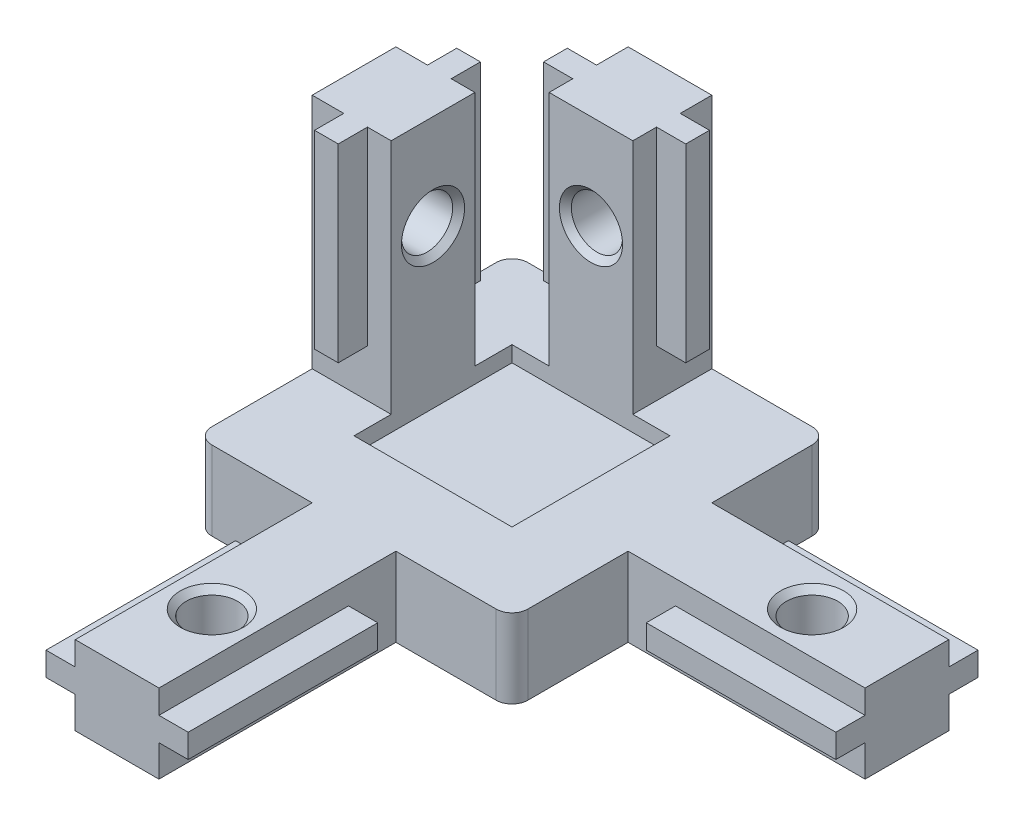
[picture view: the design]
ISO-10303-21;
HEADER;
FILE_DESCRIPTION(('STEP AP214'),'2;1');
FILE_NAME('part.step','',(''),(''),'','','');
FILE_SCHEMA(('AUTOMOTIVE_DESIGN { 1 0 10303 214 1 1 1 1 }'));
ENDSEC;
DATA;
#1=APPLICATION_CONTEXT('core data for automotive mechanical design processes');
#2=APPLICATION_PROTOCOL_DEFINITION('international standard','automotive_design',2000,#1);
#3=PRODUCT_CONTEXT('',#1,'mechanical');
#4=PRODUCT('Part','Part','',(#3));
#5=PRODUCT_RELATED_PRODUCT_CATEGORY('part','',(#4));
#6=PRODUCT_DEFINITION_FORMATION('','',#4);
#7=PRODUCT_DEFINITION_CONTEXT('part definition',#1,'design');
#8=PRODUCT_DEFINITION('design','',#6,#7);
#9=PRODUCT_DEFINITION_SHAPE('','',#8);
#10=(LENGTH_UNIT() NAMED_UNIT(*) SI_UNIT(.MILLI.,.METRE.));
#11=(NAMED_UNIT(*) PLANE_ANGLE_UNIT() SI_UNIT($,.RADIAN.));
#12=(NAMED_UNIT(*) SI_UNIT($,.STERADIAN.) SOLID_ANGLE_UNIT());
#13=UNCERTAINTY_MEASURE_WITH_UNIT(LENGTH_MEASURE(1.E-05),#10,'distance_accuracy_value','');
#14=(GEOMETRIC_REPRESENTATION_CONTEXT(3) GLOBAL_UNCERTAINTY_ASSIGNED_CONTEXT((#13)) GLOBAL_UNIT_ASSIGNED_CONTEXT((#10,
#11,#12)) REPRESENTATION_CONTEXT('',''));
#15=CARTESIAN_POINT('',(0.,0.,0.));
#16=DIRECTION('',(0.,0.,1.));
#17=DIRECTION('',(1.,0.,0.));
#18=AXIS2_PLACEMENT_3D('',#15,#16,#17);
#19=CARTESIAN_POINT('',(2.65,5.,35.));
#20=DIRECTION('',(0.,-1.,0.));
#21=DIRECTION('',(0.,0.,-1.));
#22=AXIS2_PLACEMENT_3D('',#19,#20,#21);
#23=PLANE('',#22);
#24=DIRECTION('',(0.,0.,1.));
#25=VECTOR('',#24,1.);
#26=CARTESIAN_POINT('',(-5.,5.,5.));
#27=LINE('',#26,#25);
#28=CARTESIAN_POINT('',(-5.,5.,5.));
#29=VERTEX_POINT('',#28);
#30=CARTESIAN_POINT('',(-5.,5.,7.35));
#31=VERTEX_POINT('',#30);
#32=EDGE_CURVE('E7',#29,#31,#27,.T.);
#33=ORIENTED_EDGE('',*,*,#32,.F.);
#34=DIRECTION('',(-1.,0.,0.));
#35=VECTOR('',#34,1.);
#36=CARTESIAN_POINT('',(-2.65,5.,5.));
#37=LINE('',#36,#35);
#38=CARTESIAN_POINT('',(-2.65,5.,5.));
#39=VERTEX_POINT('',#38);
#40=EDGE_CURVE('E14',#39,#29,#37,.T.);
#41=ORIENTED_EDGE('',*,*,#40,.F.);
#42=DIRECTION('',(0.,0.,1.));
#43=VECTOR('',#42,1.);
#44=CARTESIAN_POINT('',(-2.65,5.,0.));
#45=LINE('',#44,#43);
#46=CARTESIAN_POINT('',(-2.65,5.,0.));
#47=VERTEX_POINT('',#46);
#48=EDGE_CURVE('E21',#47,#39,#45,.T.);
#49=ORIENTED_EDGE('',*,*,#48,.F.);
#50=DIRECTION('',(-1.,0.,0.));
#51=VECTOR('',#50,1.);
#52=CARTESIAN_POINT('',(-2.65,5.,0.));
#53=LINE('',#52,#51);
#54=CARTESIAN_POINT('',(-9.,5.,0.));
#55=VERTEX_POINT('',#54);
#56=EDGE_CURVE('E28',#47,#55,#53,.T.);
#57=ORIENTED_EDGE('',*,*,#56,.T.);
#58=CARTESIAN_POINT('',(-9.,5.,1.00000000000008));
#59=DIRECTION('',(0.,1.,0.));
#60=DIRECTION('',(0.,0.,-1.));
#61=AXIS2_PLACEMENT_3D('',#58,#59,#60);
#62=CIRCLE('',#61,1.00000000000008);
#63=CARTESIAN_POINT('',(-10.,5.,1.));
#64=VERTEX_POINT('',#63);
#65=EDGE_CURVE('E35',#55,#64,#62,.T.);
#66=ORIENTED_EDGE('',*,*,#65,.T.);
#67=DIRECTION('',(0.,0.,1.));
#68=VECTOR('',#67,1.);
#69=CARTESIAN_POINT('',(-10.,5.,1.));
#70=LINE('',#69,#68);
#71=CARTESIAN_POINT('',(-10.,5.,7.35));
#72=VERTEX_POINT('',#71);
#73=EDGE_CURVE('E42',#64,#72,#70,.T.);
#74=ORIENTED_EDGE('',*,*,#73,.T.);
#75=DIRECTION('',(-1.,0.,0.));
#76=VECTOR('',#75,1.);
#77=CARTESIAN_POINT('',(-5.,5.,7.35));
#78=LINE('',#77,#76);
#79=EDGE_CURVE('E49',#31,#72,#78,.T.);
#80=ORIENTED_EDGE('',*,*,#79,.F.);
#81=EDGE_LOOP('',(#33,#41,#49,#57,#66,#74,#80));
#82=FACE_BOUND('',#81,.T.);
#83=ADVANCED_FACE('F55',(#82),#23,.F.);
#84=CARTESIAN_POINT('',(10.,5.,19.));
#85=DIRECTION('',(-1.,0.,0.));
#86=DIRECTION('',(0.,0.,1.));
#87=AXIS2_PLACEMENT_3D('',#84,#85,#86);
#88=PLANE('',#87);
#89=DIRECTION('',(0.,-1.,0.));
#90=VECTOR('',#89,1.);
#91=CARTESIAN_POINT('',(10.,5.,12.65));
#92=LINE('',#91,#90);
#93=CARTESIAN_POINT('',(10.,5.,12.65));
#94=VERTEX_POINT('',#93);
#95=CARTESIAN_POINT('',(10.,0.,12.65));
#96=VERTEX_POINT('',#95);
#97=EDGE_CURVE('E68',#94,#96,#92,.T.);
#98=ORIENTED_EDGE('',*,*,#97,.F.);
#99=DIRECTION('',(0.,0.,-1.));
#100=VECTOR('',#99,1.);
#101=CARTESIAN_POINT('',(10.,5.,19.));
#102=LINE('',#101,#100);
#103=CARTESIAN_POINT('',(10.,5.,19.));
#104=VERTEX_POINT('',#103);
#105=EDGE_CURVE('E75',#104,#94,#102,.T.);
#106=ORIENTED_EDGE('',*,*,#105,.F.);
#107=DIRECTION('',(0.,-1.,0.));
#108=VECTOR('',#107,1.);
#109=CARTESIAN_POINT('',(10.,5.,19.));
#110=LINE('',#109,#108);
#111=CARTESIAN_POINT('',(10.,0.,19.));
#112=VERTEX_POINT('',#111);
#113=EDGE_CURVE('E82',#104,#112,#110,.T.);
#114=ORIENTED_EDGE('',*,*,#113,.T.);
#115=DIRECTION('',(0.,0.,-1.));
#116=VECTOR('',#115,1.);
#117=CARTESIAN_POINT('',(10.,0.,19.));
#118=LINE('',#117,#116);
#119=EDGE_CURVE('E89',#112,#96,#118,.T.);
#120=ORIENTED_EDGE('',*,*,#119,.T.);
#121=EDGE_LOOP('',(#98,#106,#114,#120));
#122=FACE_BOUND('',#121,.T.);
#123=ADVANCED_FACE('F95',(#122),#88,.F.);
#124=DIRECTION('',(0.,1.,0.));
#125=VECTOR('',#124,1.);
#126=CARTESIAN_POINT('',(10.,0.,7.35));
#127=LINE('',#126,#125);
#128=CARTESIAN_POINT('',(10.,0.,7.35));
#129=VERTEX_POINT('',#128);
#130=CARTESIAN_POINT('',(10.,5.,7.35));
#131=VERTEX_POINT('',#130);
#132=EDGE_CURVE('E104',#129,#131,#127,.T.);
#133=ORIENTED_EDGE('',*,*,#132,.F.);
#134=DIRECTION('',(0.,0.,-1.));
#135=VECTOR('',#134,1.);
#136=CARTESIAN_POINT('',(10.,0.,7.35));
#137=LINE('',#136,#135);
#138=CARTESIAN_POINT('',(10.,0.,1.));
#139=VERTEX_POINT('',#138);
#140=EDGE_CURVE('E111',#129,#139,#137,.T.);
#141=ORIENTED_EDGE('',*,*,#140,.T.);
#142=DIRECTION('',(0.,-1.,0.));
#143=VECTOR('',#142,1.);
#144=CARTESIAN_POINT('',(10.,5.,1.));
#145=LINE('',#144,#143);
#146=CARTESIAN_POINT('',(10.,5.,1.));
#147=VERTEX_POINT('',#146);
#148=EDGE_CURVE('E118',#147,#139,#145,.T.);
#149=ORIENTED_EDGE('',*,*,#148,.F.);
#150=DIRECTION('',(0.,0.,-1.));
#151=VECTOR('',#150,1.);
#152=CARTESIAN_POINT('',(10.,5.,7.35));
#153=LINE('',#152,#151);
#154=EDGE_CURVE('E125',#131,#147,#153,.T.);
#155=ORIENTED_EDGE('',*,*,#154,.F.);
#156=EDGE_LOOP('',(#133,#141,#149,#155));
#157=FACE_BOUND('',#156,.T.);
#158=ADVANCED_FACE('F130',(#157),#88,.F.);
#159=CARTESIAN_POINT('',(19.,5.,10.));
#160=DIRECTION('',(0.,-1.,0.));
#161=DIRECTION('',(0.,0.,-1.));
#162=AXIS2_PLACEMENT_3D('',#159,#160,#161);
#163=CIRCLE('',#162,2.);
#164=CARTESIAN_POINT('',(19.,5.,8.));
#165=VERTEX_POINT('',#164);
#166=EDGE_CURVE('E137',#165,#165,#163,.T.);
#167=ORIENTED_EDGE('',*,*,#166,.T.);
#168=EDGE_LOOP('',(#167));
#169=FACE_BOUND('',#168,.T.);
#170=DIRECTION('',(0.,0.,-1.));
#171=VECTOR('',#170,1.);
#172=CARTESIAN_POINT('',(2.65,5.,5.));
#173=LINE('',#172,#171);
#174=CARTESIAN_POINT('',(2.65,5.,5.));
#175=VERTEX_POINT('',#174);
#176=CARTESIAN_POINT('',(2.65,5.,0.));
#177=VERTEX_POINT('',#176);
#178=EDGE_CURVE('E143',#175,#177,#173,.T.);
#179=ORIENTED_EDGE('',*,*,#178,.F.);
#180=DIRECTION('',(-1.,0.,0.));
#181=VECTOR('',#180,1.);
#182=CARTESIAN_POINT('',(5.,5.,5.));
#183=LINE('',#182,#181);
#184=CARTESIAN_POINT('',(5.,5.,5.));
#185=VERTEX_POINT('',#184);
#186=EDGE_CURVE('E150',#185,#175,#183,.T.);
#187=ORIENTED_EDGE('',*,*,#186,.F.);
#188=DIRECTION('',(0.,0.,-1.));
#189=VECTOR('',#188,1.);
#190=CARTESIAN_POINT('',(5.,5.,15.));
#191=LINE('',#190,#189);
#192=CARTESIAN_POINT('',(5.,5.,15.));
#193=VERTEX_POINT('',#192);
#194=EDGE_CURVE('E157',#193,#185,#191,.T.);
#195=ORIENTED_EDGE('',*,*,#194,.F.);
#196=DIRECTION('',(1.,0.,0.));
#197=VECTOR('',#196,1.);
#198=CARTESIAN_POINT('',(-5.,5.,15.));
#199=LINE('',#198,#197);
#200=CARTESIAN_POINT('',(-5.,5.,15.));
#201=VERTEX_POINT('',#200);
#202=EDGE_CURVE('E164',#201,#193,#199,.T.);
#203=ORIENTED_EDGE('',*,*,#202,.F.);
#204=DIRECTION('',(0.,0.,1.));
#205=VECTOR('',#204,1.);
#206=CARTESIAN_POINT('',(-5.,5.,12.65));
#207=LINE('',#206,#205);
#208=CARTESIAN_POINT('',(-5.,5.,12.65));
#209=VERTEX_POINT('',#208);
#210=EDGE_CURVE('E171',#209,#201,#207,.T.);
#211=ORIENTED_EDGE('',*,*,#210,.F.);
#212=DIRECTION('',(1.,0.,0.));
#213=VECTOR('',#212,1.);
#214=CARTESIAN_POINT('',(-10.,5.,12.65));
#215=LINE('',#214,#213);
#216=CARTESIAN_POINT('',(-10.,5.,12.65));
#217=VERTEX_POINT('',#216);
#218=EDGE_CURVE('E178',#217,#209,#215,.T.);
#219=ORIENTED_EDGE('',*,*,#218,.F.);
#220=DIRECTION('',(0.,0.,1.));
#221=VECTOR('',#220,1.);
#222=CARTESIAN_POINT('',(-10.,5.,12.65));
#223=LINE('',#222,#221);
#224=CARTESIAN_POINT('',(-10.,5.,19.));
#225=VERTEX_POINT('',#224);
#226=EDGE_CURVE('E185',#217,#225,#223,.T.);
#227=ORIENTED_EDGE('',*,*,#226,.T.);
#228=CARTESIAN_POINT('',(-9.0000000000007,5.,19.0000000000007));
#229=DIRECTION('',(0.,1.,0.));
#230=DIRECTION('',(-1.,0.,-6.99884594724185E-13));
#231=AXIS2_PLACEMENT_3D('',#228,#229,#230);
#232=CIRCLE('',#231,0.999999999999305);
#233=CARTESIAN_POINT('',(-9.,5.,20.));
#234=VERTEX_POINT('',#233);
#235=EDGE_CURVE('E192',#225,#234,#232,.T.);
#236=ORIENTED_EDGE('',*,*,#235,.T.);
#237=DIRECTION('',(1.,0.,0.));
#238=VECTOR('',#237,1.);
#239=CARTESIAN_POINT('',(-9.,5.,20.));
#240=LINE('',#239,#238);
#241=CARTESIAN_POINT('',(-2.65,5.,20.));
#242=VERTEX_POINT('',#241);
#243=EDGE_CURVE('E199',#234,#242,#240,.T.);
#244=ORIENTED_EDGE('',*,*,#243,.T.);
#245=DIRECTION('',(0.,0.,-1.));
#246=VECTOR('',#245,1.);
#247=CARTESIAN_POINT('',(-2.65,5.,35.));
#248=LINE('',#247,#246);
#249=CARTESIAN_POINT('',(-2.65,5.,35.));
#250=VERTEX_POINT('',#249);
#251=EDGE_CURVE('E206',#250,#242,#248,.T.);
#252=ORIENTED_EDGE('',*,*,#251,.F.);
#253=DIRECTION('',(-1.,0.,0.));
#254=VECTOR('',#253,1.);
#255=CARTESIAN_POINT('',(2.65,5.,35.));
#256=LINE('',#255,#254);
#257=CARTESIAN_POINT('',(2.65,5.,35.));
#258=VERTEX_POINT('',#257);
#259=EDGE_CURVE('E213',#258,#250,#256,.T.);
#260=ORIENTED_EDGE('',*,*,#259,.F.);
#261=DIRECTION('',(0.,0.,-1.));
#262=VECTOR('',#261,1.);
#263=CARTESIAN_POINT('',(2.65,5.,35.));
#264=LINE('',#263,#262);
#265=CARTESIAN_POINT('',(2.65,5.,20.));
#266=VERTEX_POINT('',#265);
#267=EDGE_CURVE('E220',#258,#266,#264,.T.);
#268=ORIENTED_EDGE('',*,*,#267,.T.);
#269=DIRECTION('',(1.,0.,0.));
#270=VECTOR('',#269,1.);
#271=CARTESIAN_POINT('',(2.65,5.,20.));
#272=LINE('',#271,#270);
#273=CARTESIAN_POINT('',(9.,5.,20.));
#274=VERTEX_POINT('',#273);
#275=EDGE_CURVE('E227',#266,#274,#272,.T.);
#276=ORIENTED_EDGE('',*,*,#275,.T.);
#277=CARTESIAN_POINT('',(9.0000000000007,5.,19.0000000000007));
#278=DIRECTION('',(0.,1.,0.));
#279=DIRECTION('',(-6.99884594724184E-13,0.,1.));
#280=AXIS2_PLACEMENT_3D('',#277,#278,#279);
#281=CIRCLE('',#280,0.999999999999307);
#282=EDGE_CURVE('E234',#274,#104,#281,.T.);
#283=ORIENTED_EDGE('',*,*,#282,.T.);
#284=ORIENTED_EDGE('',*,*,#105,.T.);
#285=DIRECTION('',(-1.,0.,0.));
#286=VECTOR('',#285,1.);
#287=CARTESIAN_POINT('',(25.,5.,12.65));
#288=LINE('',#287,#286);
#289=CARTESIAN_POINT('',(25.,5.,12.65));
#290=VERTEX_POINT('',#289);
#291=EDGE_CURVE('E240',#290,#94,#288,.T.);
#292=ORIENTED_EDGE('',*,*,#291,.F.);
#293=DIRECTION('',(0.,0.,1.));
#294=VECTOR('',#293,1.);
#295=CARTESIAN_POINT('',(25.,5.,7.35));
#296=LINE('',#295,#294);
#297=CARTESIAN_POINT('',(25.,5.,7.35));
#298=VERTEX_POINT('',#297);
#299=EDGE_CURVE('E247',#298,#290,#296,.T.);
#300=ORIENTED_EDGE('',*,*,#299,.F.);
#301=DIRECTION('',(-1.,0.,0.));
#302=VECTOR('',#301,1.);
#303=CARTESIAN_POINT('',(25.,5.,7.35));
#304=LINE('',#303,#302);
#305=EDGE_CURVE('E254',#298,#131,#304,.T.);
#306=ORIENTED_EDGE('',*,*,#305,.T.);
#307=ORIENTED_EDGE('',*,*,#154,.T.);
#308=CARTESIAN_POINT('',(9.,5.,1.00000000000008));
#309=DIRECTION('',(0.,1.,0.));
#310=DIRECTION('',(1.,0.,0.));
#311=AXIS2_PLACEMENT_3D('',#308,#309,#310);
#312=CIRCLE('',#311,1.00000000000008);
#313=CARTESIAN_POINT('',(9.,5.,0.));
#314=VERTEX_POINT('',#313);
#315=EDGE_CURVE('E260',#147,#314,#312,.T.);
#316=ORIENTED_EDGE('',*,*,#315,.T.);
#317=DIRECTION('',(-1.,0.,0.));
#318=VECTOR('',#317,1.);
#319=CARTESIAN_POINT('',(9.,5.,0.));
#320=LINE('',#319,#318);
#321=EDGE_CURVE('E267',#314,#177,#320,.T.);
#322=ORIENTED_EDGE('',*,*,#321,.T.);
#323=EDGE_LOOP('',(#179,#187,#195,#203,#211,#219,#227,#236,#244,#252,#260,#268,#276,#283,#284,
#292,#300,#306,#307,#316,#322));
#324=FACE_BOUND('',#323,.T.);
#325=CARTESIAN_POINT('',(0.,5.,29.));
#326=DIRECTION('',(0.,1.,0.));
#327=DIRECTION('',(0.,0.,1.));
#328=AXIS2_PLACEMENT_3D('',#325,#326,#327);
#329=CIRCLE('',#328,2.);
#330=CARTESIAN_POINT('',(0.,5.,31.));
#331=VERTEX_POINT('',#330);
#332=EDGE_CURVE('E273',#331,#331,#329,.T.);
#333=ORIENTED_EDGE('',*,*,#332,.F.);
#334=EDGE_LOOP('',(#333));
#335=FACE_BOUND('',#334,.T.);
#336=ADVANCED_FACE('F276',(#169,#324,#335),#23,.F.);
#337=CARTESIAN_POINT('',(-2.65,5.,35.));
#338=DIRECTION('',(1.,0.,0.));
#339=DIRECTION('',(0.,0.,-1.));
#340=AXIS2_PLACEMENT_3D('',#337,#338,#339);
#341=PLANE('',#340);
#342=DIRECTION('',(0.,-1.,0.));
#343=VECTOR('',#342,1.);
#344=CARTESIAN_POINT('',(-2.65,2.,35.));
#345=LINE('',#344,#343);
#346=CARTESIAN_POINT('',(-2.65,2.,35.));
#347=VERTEX_POINT('',#346);
#348=CARTESIAN_POINT('',(-2.65,0.,35.));
#349=VERTEX_POINT('',#348);
#350=EDGE_CURVE('E285',#347,#349,#345,.T.);
#351=ORIENTED_EDGE('',*,*,#350,.F.);
#352=DIRECTION('',(0.,0.,-1.));
#353=VECTOR('',#352,1.);
#354=CARTESIAN_POINT('',(-2.65,2.,35.));
#355=LINE('',#354,#353);
#356=CARTESIAN_POINT('',(-2.65,2.,23.));
#357=VERTEX_POINT('',#356);
#358=EDGE_CURVE('E292',#347,#357,#355,.T.);
#359=ORIENTED_EDGE('',*,*,#358,.T.);
#360=DIRECTION('',(0.,-1.,0.));
#361=VECTOR('',#360,1.);
#362=CARTESIAN_POINT('',(-2.65,3.5,23.));
#363=LINE('',#362,#361);
#364=CARTESIAN_POINT('',(-2.65,3.5,23.));
#365=VERTEX_POINT('',#364);
#366=EDGE_CURVE('E299',#365,#357,#363,.T.);
#367=ORIENTED_EDGE('',*,*,#366,.F.);
#368=DIRECTION('',(0.,0.,1.));
#369=VECTOR('',#368,1.);
#370=CARTESIAN_POINT('',(-2.65,3.5,23.));
#371=LINE('',#370,#369);
#372=CARTESIAN_POINT('',(-2.65,3.5,35.));
#373=VERTEX_POINT('',#372);
#374=EDGE_CURVE('E306',#365,#373,#371,.T.);
#375=ORIENTED_EDGE('',*,*,#374,.T.);
#376=DIRECTION('',(0.,-1.,0.));
#377=VECTOR('',#376,1.);
#378=CARTESIAN_POINT('',(-2.65,5.,35.));
#379=LINE('',#378,#377);
#380=EDGE_CURVE('E313',#250,#373,#379,.T.);
#381=ORIENTED_EDGE('',*,*,#380,.F.);
#382=ORIENTED_EDGE('',*,*,#251,.T.);
#383=DIRECTION('',(0.,1.,0.));
#384=VECTOR('',#383,1.);
#385=CARTESIAN_POINT('',(-2.65,0.,20.));
#386=LINE('',#385,#384);
#387=CARTESIAN_POINT('',(-2.65,0.,20.));
#388=VERTEX_POINT('',#387);
#389=EDGE_CURVE('E319',#388,#242,#386,.T.);
#390=ORIENTED_EDGE('',*,*,#389,.F.);
#391=DIRECTION('',(0.,0.,-1.));
#392=VECTOR('',#391,1.);
#393=CARTESIAN_POINT('',(-2.65,0.,35.));
#394=LINE('',#393,#392);
#395=EDGE_CURVE('E326',#349,#388,#394,.T.);
#396=ORIENTED_EDGE('',*,*,#395,.F.);
#397=EDGE_LOOP('',(#351,#359,#367,#375,#381,#382,#390,#396));
#398=FACE_BOUND('',#397,.T.);
#399=ADVANCED_FACE('F332',(#398),#341,.F.);
#400=CARTESIAN_POINT('',(2.65,0.,35.));
#401=DIRECTION('',(-1.,0.,0.));
#402=DIRECTION('',(0.,0.,1.));
#403=AXIS2_PLACEMENT_3D('',#400,#401,#402);
#404=PLANE('',#403);
#405=DIRECTION('',(0.,1.,0.));
#406=VECTOR('',#405,1.);
#407=CARTESIAN_POINT('',(2.65,2.,23.));
#408=LINE('',#407,#406);
#409=CARTESIAN_POINT('',(2.65,2.,23.));
#410=VERTEX_POINT('',#409);
#411=CARTESIAN_POINT('',(2.65,3.5,23.));
#412=VERTEX_POINT('',#411);
#413=EDGE_CURVE('E341',#410,#412,#408,.T.);
#414=ORIENTED_EDGE('',*,*,#413,.F.);
#415=DIRECTION('',(0.,0.,1.));
#416=VECTOR('',#415,1.);
#417=CARTESIAN_POINT('',(2.65,2.,23.));
#418=LINE('',#417,#416);
#419=CARTESIAN_POINT('',(2.65,2.,35.));
#420=VERTEX_POINT('',#419);
#421=EDGE_CURVE('E348',#410,#420,#418,.T.);
#422=ORIENTED_EDGE('',*,*,#421,.T.);
#423=DIRECTION('',(0.,1.,0.));
#424=VECTOR('',#423,1.);
#425=CARTESIAN_POINT('',(2.65,0.,35.));
#426=LINE('',#425,#424);
#427=CARTESIAN_POINT('',(2.65,0.,35.));
#428=VERTEX_POINT('',#427);
#429=EDGE_CURVE('E355',#428,#420,#426,.T.);
#430=ORIENTED_EDGE('',*,*,#429,.F.);
#431=DIRECTION('',(0.,0.,-1.));
#432=VECTOR('',#431,1.);
#433=CARTESIAN_POINT('',(2.65,0.,35.));
#434=LINE('',#433,#432);
#435=CARTESIAN_POINT('',(2.65,0.,20.));
#436=VERTEX_POINT('',#435);
#437=EDGE_CURVE('E362',#428,#436,#434,.T.);
#438=ORIENTED_EDGE('',*,*,#437,.T.);
#439=DIRECTION('',(0.,-1.,0.));
#440=VECTOR('',#439,1.);
#441=CARTESIAN_POINT('',(2.65,5.,20.));
#442=LINE('',#441,#440);
#443=EDGE_CURVE('E369',#266,#436,#442,.T.);
#444=ORIENTED_EDGE('',*,*,#443,.F.);
#445=ORIENTED_EDGE('',*,*,#267,.F.);
#446=DIRECTION('',(0.,1.,0.));
#447=VECTOR('',#446,1.);
#448=CARTESIAN_POINT('',(2.65,3.5,35.));
#449=LINE('',#448,#447);
#450=CARTESIAN_POINT('',(2.65,3.5,35.));
#451=VERTEX_POINT('',#450);
#452=EDGE_CURVE('E375',#451,#258,#449,.T.);
#453=ORIENTED_EDGE('',*,*,#452,.F.);
#454=DIRECTION('',(0.,0.,-1.));
#455=VECTOR('',#454,1.);
#456=CARTESIAN_POINT('',(2.65,3.5,35.));
#457=LINE('',#456,#455);
#458=EDGE_CURVE('E382',#451,#412,#457,.T.);
#459=ORIENTED_EDGE('',*,*,#458,.T.);
#460=EDGE_LOOP('',(#414,#422,#430,#438,#444,#445,#453,#459));
#461=FACE_BOUND('',#460,.T.);
#462=ADVANCED_FACE('F388',(#461),#404,.F.);
#463=CARTESIAN_POINT('',(-2.65,0.,35.));
#464=DIRECTION('',(0.,1.,0.));
#465=DIRECTION('',(0.,0.,1.));
#466=AXIS2_PLACEMENT_3D('',#463,#464,#465);
#467=PLANE('',#466);
#468=CARTESIAN_POINT('',(19.,0.,10.));
#469=DIRECTION('',(0.,-1.,0.));
#470=DIRECTION('',(0.,0.,-1.));
#471=AXIS2_PLACEMENT_3D('',#468,#469,#470);
#472=CIRCLE('',#471,2.);
#473=CARTESIAN_POINT('',(19.,0.,8.));
#474=VERTEX_POINT('',#473);
#475=EDGE_CURVE('E395',#474,#474,#472,.T.);
#476=ORIENTED_EDGE('',*,*,#475,.F.);
#477=EDGE_LOOP('',(#476));
#478=FACE_BOUND('',#477,.T.);
#479=CARTESIAN_POINT('',(-9.0000000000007,0.,19.0000000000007));
#480=DIRECTION('',(0.,1.,0.));
#481=DIRECTION('',(-1.,0.,-6.99884594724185E-13));
#482=AXIS2_PLACEMENT_3D('',#479,#480,#481);
#483=CIRCLE('',#482,0.999999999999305);
#484=CARTESIAN_POINT('',(-10.,0.,19.));
#485=VERTEX_POINT('',#484);
#486=CARTESIAN_POINT('',(-9.,0.,20.));
#487=VERTEX_POINT('',#486);
#488=EDGE_CURVE('E401',#485,#487,#483,.T.);
#489=ORIENTED_EDGE('',*,*,#488,.F.);
#490=DIRECTION('',(0.,0.,1.));
#491=VECTOR('',#490,1.);
#492=CARTESIAN_POINT('',(-10.,0.,1.));
#493=LINE('',#492,#491);
#494=CARTESIAN_POINT('',(-10.,0.,1.));
#495=VERTEX_POINT('',#494);
#496=EDGE_CURVE('E408',#495,#485,#493,.T.);
#497=ORIENTED_EDGE('',*,*,#496,.F.);
#498=CARTESIAN_POINT('',(-9.,0.,1.00000000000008));
#499=DIRECTION('',(0.,1.,0.));
#500=DIRECTION('',(0.,0.,-1.));
#501=AXIS2_PLACEMENT_3D('',#498,#499,#500);
#502=CIRCLE('',#501,1.00000000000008);
#503=CARTESIAN_POINT('',(-9.,0.,0.));
#504=VERTEX_POINT('',#503);
#505=EDGE_CURVE('E415',#504,#495,#502,.T.);
#506=ORIENTED_EDGE('',*,*,#505,.F.);
#507=DIRECTION('',(1.,0.,0.));
#508=VECTOR('',#507,1.);
#509=CARTESIAN_POINT('',(-9.,0.,0.));
#510=LINE('',#509,#508);
#511=CARTESIAN_POINT('',(9.,0.,0.));
#512=VERTEX_POINT('',#511);
#513=EDGE_CURVE('E422',#504,#512,#510,.T.);
#514=ORIENTED_EDGE('',*,*,#513,.T.);
#515=CARTESIAN_POINT('',(9.,0.,1.00000000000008));
#516=DIRECTION('',(0.,1.,0.));
#517=DIRECTION('',(1.,0.,0.));
#518=AXIS2_PLACEMENT_3D('',#515,#516,#517);
#519=CIRCLE('',#518,1.00000000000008);
#520=EDGE_CURVE('E429',#139,#512,#519,.T.);
#521=ORIENTED_EDGE('',*,*,#520,.F.);
#522=ORIENTED_EDGE('',*,*,#140,.F.);
#523=DIRECTION('',(-1.,0.,0.));
#524=VECTOR('',#523,1.);
#525=CARTESIAN_POINT('',(25.,0.,7.35));
#526=LINE('',#525,#524);
#527=CARTESIAN_POINT('',(25.,0.,7.35));
#528=VERTEX_POINT('',#527);
#529=EDGE_CURVE('E435',#528,#129,#526,.T.);
#530=ORIENTED_EDGE('',*,*,#529,.F.);
#531=DIRECTION('',(0.,0.,-1.));
#532=VECTOR('',#531,1.);
#533=CARTESIAN_POINT('',(25.,0.,12.65));
#534=LINE('',#533,#532);
#535=CARTESIAN_POINT('',(25.,0.,12.65));
#536=VERTEX_POINT('',#535);
#537=EDGE_CURVE('E442',#536,#528,#534,.T.);
#538=ORIENTED_EDGE('',*,*,#537,.F.);
#539=DIRECTION('',(-1.,0.,0.));
#540=VECTOR('',#539,1.);
#541=CARTESIAN_POINT('',(25.,0.,12.65));
#542=LINE('',#541,#540);
#543=EDGE_CURVE('E449',#536,#96,#542,.T.);
#544=ORIENTED_EDGE('',*,*,#543,.T.);
#545=ORIENTED_EDGE('',*,*,#119,.F.);
#546=CARTESIAN_POINT('',(9.0000000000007,0.,19.0000000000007));
#547=DIRECTION('',(0.,1.,0.));
#548=DIRECTION('',(-6.99884594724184E-13,0.,1.));
#549=AXIS2_PLACEMENT_3D('',#546,#547,#548);
#550=CIRCLE('',#549,0.999999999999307);
#551=CARTESIAN_POINT('',(9.,0.,20.));
#552=VERTEX_POINT('',#551);
#553=EDGE_CURVE('E455',#552,#112,#550,.T.);
#554=ORIENTED_EDGE('',*,*,#553,.F.);
#555=DIRECTION('',(1.,0.,0.));
#556=VECTOR('',#555,1.);
#557=CARTESIAN_POINT('',(2.65,0.,20.));
#558=LINE('',#557,#556);
#559=EDGE_CURVE('E462',#436,#552,#558,.T.);
#560=ORIENTED_EDGE('',*,*,#559,.F.);
#561=ORIENTED_EDGE('',*,*,#437,.F.);
#562=DIRECTION('',(1.,0.,0.));
#563=VECTOR('',#562,1.);
#564=CARTESIAN_POINT('',(-2.65,0.,35.));
#565=LINE('',#564,#563);
#566=EDGE_CURVE('E468',#349,#428,#565,.T.);
#567=ORIENTED_EDGE('',*,*,#566,.F.);
#568=ORIENTED_EDGE('',*,*,#395,.T.);
#569=DIRECTION('',(1.,0.,0.));
#570=VECTOR('',#569,1.);
#571=CARTESIAN_POINT('',(-9.,0.,20.));
#572=LINE('',#571,#570);
#573=EDGE_CURVE('E474',#487,#388,#572,.T.);
#574=ORIENTED_EDGE('',*,*,#573,.F.);
#575=EDGE_LOOP('',(#489,#497,#506,#514,#521,#522,#530,#538,#544,#545,#554,#560,#561,#567,#568,#574));
#576=FACE_BOUND('',#575,.T.);
#577=CARTESIAN_POINT('',(0.,0.,29.));
#578=DIRECTION('',(0.,1.,0.));
#579=DIRECTION('',(0.,0.,1.));
#580=AXIS2_PLACEMENT_3D('',#577,#578,#579);
#581=CIRCLE('',#580,2.);
#582=CARTESIAN_POINT('',(0.,0.,31.));
#583=VERTEX_POINT('',#582);
#584=EDGE_CURVE('E480',#583,#583,#581,.T.);
#585=ORIENTED_EDGE('',*,*,#584,.T.);
#586=EDGE_LOOP('',(#585));
#587=FACE_BOUND('',#586,.T.);
#588=ADVANCED_FACE('F484',(#478,#576,#587),#467,.F.);
#589=CARTESIAN_POINT('',(0.,0.,35.));
#590=DIRECTION('',(0.,0.,1.));
#591=DIRECTION('',(1.,0.,0.));
#592=AXIS2_PLACEMENT_3D('',#589,#590,#591);
#593=PLANE('',#592);
#594=ORIENTED_EDGE('',*,*,#380,.T.);
#595=DIRECTION('',(-1.,0.,0.));
#596=VECTOR('',#595,1.);
#597=CARTESIAN_POINT('',(-2.65,3.5,35.));
#598=LINE('',#597,#596);
#599=CARTESIAN_POINT('',(-4.5,3.5,35.));
#600=VERTEX_POINT('',#599);
#601=EDGE_CURVE('E494',#373,#600,#598,.T.);
#602=ORIENTED_EDGE('',*,*,#601,.T.);
#603=DIRECTION('',(0.,-1.,0.));
#604=VECTOR('',#603,1.);
#605=CARTESIAN_POINT('',(-4.5,3.5,35.));
#606=LINE('',#605,#604);
#607=CARTESIAN_POINT('',(-4.5,2.,35.));
#608=VERTEX_POINT('',#607);
#609=EDGE_CURVE('E501',#600,#608,#606,.T.);
#610=ORIENTED_EDGE('',*,*,#609,.T.);
#611=DIRECTION('',(1.,0.,0.));
#612=VECTOR('',#611,1.);
#613=CARTESIAN_POINT('',(-4.5,2.,35.));
#614=LINE('',#613,#612);
#615=EDGE_CURVE('E508',#608,#347,#614,.T.);
#616=ORIENTED_EDGE('',*,*,#615,.T.);
#617=ORIENTED_EDGE('',*,*,#350,.T.);
#618=ORIENTED_EDGE('',*,*,#566,.T.);
#619=ORIENTED_EDGE('',*,*,#429,.T.);
#620=DIRECTION('',(1.,0.,0.));
#621=VECTOR('',#620,1.);
#622=CARTESIAN_POINT('',(2.65,2.,35.));
#623=LINE('',#622,#621);
#624=CARTESIAN_POINT('',(4.5,2.,35.));
#625=VERTEX_POINT('',#624);
#626=EDGE_CURVE('E516',#420,#625,#623,.T.);
#627=ORIENTED_EDGE('',*,*,#626,.T.);
#628=DIRECTION('',(0.,1.,0.));
#629=VECTOR('',#628,1.);
#630=CARTESIAN_POINT('',(4.5,2.,35.));
#631=LINE('',#630,#629);
#632=CARTESIAN_POINT('',(4.5,3.5,35.));
#633=VERTEX_POINT('',#632);
#634=EDGE_CURVE('E523',#625,#633,#631,.T.);
#635=ORIENTED_EDGE('',*,*,#634,.T.);
#636=DIRECTION('',(-1.,0.,0.));
#637=VECTOR('',#636,1.);
#638=CARTESIAN_POINT('',(4.5,3.5,35.));
#639=LINE('',#638,#637);
#640=EDGE_CURVE('E530',#633,#451,#639,.T.);
#641=ORIENTED_EDGE('',*,*,#640,.T.);
#642=ORIENTED_EDGE('',*,*,#452,.T.);
#643=ORIENTED_EDGE('',*,*,#259,.T.);
#644=EDGE_LOOP('',(#594,#602,#610,#616,#617,#618,#619,#627,#635,#641,#642,#643));
#645=FACE_BOUND('',#644,.T.);
#646=ADVANCED_FACE('F536',(#645),#593,.T.);
#647=CARTESIAN_POINT('',(0.,0.,0.));
#648=DIRECTION('',(0.,0.,1.));
#649=DIRECTION('',(1.,0.,0.));
#650=AXIS2_PLACEMENT_3D('',#647,#648,#649);
#651=PLANE('',#650);
#652=CARTESIAN_POINT('',(0.,14.,0.));
#653=DIRECTION('',(0.,0.,-1.));
#654=DIRECTION('',(-1.,0.,0.));
#655=AXIS2_PLACEMENT_3D('',#652,#653,#654);
#656=CIRCLE('',#655,2.);
#657=CARTESIAN_POINT('',(-2.,14.,0.));
#658=VERTEX_POINT('',#657);
#659=EDGE_CURVE('E543',#658,#658,#656,.T.);
#660=ORIENTED_EDGE('',*,*,#659,.F.);
#661=EDGE_LOOP('',(#660));
#662=FACE_BOUND('',#661,.T.);
#663=DIRECTION('',(0.,-1.,0.));
#664=VECTOR('',#663,1.);
#665=CARTESIAN_POINT('',(9.,5.,0.));
#666=LINE('',#665,#664);
#667=EDGE_CURVE('E549',#314,#512,#666,.T.);
#668=ORIENTED_EDGE('',*,*,#667,.T.);
#669=ORIENTED_EDGE('',*,*,#513,.F.);
#670=DIRECTION('',(0.,-1.,0.));
#671=VECTOR('',#670,1.);
#672=CARTESIAN_POINT('',(-9.,5.,0.));
#673=LINE('',#672,#671);
#674=EDGE_CURVE('E555',#55,#504,#673,.T.);
#675=ORIENTED_EDGE('',*,*,#674,.F.);
#676=ORIENTED_EDGE('',*,*,#56,.F.);
#677=DIRECTION('',(0.,-1.,0.));
#678=VECTOR('',#677,1.);
#679=CARTESIAN_POINT('',(-2.65,20.,0.));
#680=LINE('',#679,#678);
#681=CARTESIAN_POINT('',(-2.65,20.,0.));
#682=VERTEX_POINT('',#681);
#683=EDGE_CURVE('E561',#682,#47,#680,.T.);
#684=ORIENTED_EDGE('',*,*,#683,.F.);
#685=DIRECTION('',(-1.,0.,0.));
#686=VECTOR('',#685,1.);
#687=CARTESIAN_POINT('',(2.65,20.,0.));
#688=LINE('',#687,#686);
#689=CARTESIAN_POINT('',(2.65,20.,0.));
#690=VERTEX_POINT('',#689);
#691=EDGE_CURVE('E568',#690,#682,#688,.T.);
#692=ORIENTED_EDGE('',*,*,#691,.F.);
#693=DIRECTION('',(0.,-1.,0.));
#694=VECTOR('',#693,1.);
#695=CARTESIAN_POINT('',(2.65,20.,0.));
#696=LINE('',#695,#694);
#697=EDGE_CURVE('E575',#690,#177,#696,.T.);
#698=ORIENTED_EDGE('',*,*,#697,.T.);
#699=ORIENTED_EDGE('',*,*,#321,.F.);
#700=EDGE_LOOP('',(#668,#669,#675,#676,#684,#692,#698,#699));
#701=FACE_BOUND('',#700,.T.);
#702=ADVANCED_FACE('F580',(#662,#701),#651,.F.);
#703=CARTESIAN_POINT('',(9.0000000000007,5.,19.0000000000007));
#704=DIRECTION('',(0.,-1.,0.));
#705=DIRECTION('',(0.,0.,-1.));
#706=AXIS2_PLACEMENT_3D('',#703,#704,#705);
#707=CYLINDRICAL_SURFACE('',#706,0.999999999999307);
#708=ORIENTED_EDGE('',*,*,#553,.T.);
#709=ORIENTED_EDGE('',*,*,#113,.F.);
#710=ORIENTED_EDGE('',*,*,#282,.F.);
#711=DIRECTION('',(0.,-1.,0.));
#712=VECTOR('',#711,1.);
#713=CARTESIAN_POINT('',(9.,5.,20.));
#714=LINE('',#713,#712);
#715=EDGE_CURVE('E592',#274,#552,#714,.T.);
#716=ORIENTED_EDGE('',*,*,#715,.T.);
#717=EDGE_LOOP('',(#708,#709,#710,#716));
#718=FACE_BOUND('',#717,.T.);
#719=ADVANCED_FACE('F596',(#718),#707,.T.);
#720=CARTESIAN_POINT('',(9.,5.,1.00000000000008));
#721=DIRECTION('',(0.,-1.,0.));
#722=DIRECTION('',(0.,0.,-1.));
#723=AXIS2_PLACEMENT_3D('',#720,#721,#722);
#724=CYLINDRICAL_SURFACE('',#723,1.00000000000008);
#725=ORIENTED_EDGE('',*,*,#520,.T.);
#726=ORIENTED_EDGE('',*,*,#667,.F.);
#727=ORIENTED_EDGE('',*,*,#315,.F.);
#728=ORIENTED_EDGE('',*,*,#148,.T.);
#729=EDGE_LOOP('',(#725,#726,#727,#728));
#730=FACE_BOUND('',#729,.T.);
#731=ADVANCED_FACE('F608',(#730),#724,.T.);
#732=CARTESIAN_POINT('',(-9.,5.,20.));
#733=DIRECTION('',(0.,0.,-1.));
#734=DIRECTION('',(-1.,0.,0.));
#735=AXIS2_PLACEMENT_3D('',#732,#733,#734);
#736=PLANE('',#735);
#737=ORIENTED_EDGE('',*,*,#275,.F.);
#738=ORIENTED_EDGE('',*,*,#443,.T.);
#739=ORIENTED_EDGE('',*,*,#559,.T.);
#740=ORIENTED_EDGE('',*,*,#715,.F.);
#741=EDGE_LOOP('',(#737,#738,#739,#740));
#742=FACE_BOUND('',#741,.T.);
#743=ADVANCED_FACE('F620',(#742),#736,.F.);
#744=ORIENTED_EDGE('',*,*,#573,.T.);
#745=ORIENTED_EDGE('',*,*,#389,.T.);
#746=ORIENTED_EDGE('',*,*,#243,.F.);
#747=DIRECTION('',(0.,-1.,0.));
#748=VECTOR('',#747,1.);
#749=CARTESIAN_POINT('',(-9.,5.,20.));
#750=LINE('',#749,#748);
#751=EDGE_CURVE('E632',#234,#487,#750,.T.);
#752=ORIENTED_EDGE('',*,*,#751,.T.);
#753=EDGE_LOOP('',(#744,#745,#746,#752));
#754=FACE_BOUND('',#753,.T.);
#755=ADVANCED_FACE('F635',(#754),#736,.F.);
#756=CARTESIAN_POINT('',(-10.,5.,1.));
#757=DIRECTION('',(1.,0.,0.));
#758=DIRECTION('',(0.,0.,-1.));
#759=AXIS2_PLACEMENT_3D('',#756,#757,#758);
#760=PLANE('',#759);
#761=ORIENTED_EDGE('',*,*,#496,.T.);
#762=DIRECTION('',(0.,-1.,0.));
#763=VECTOR('',#762,1.);
#764=CARTESIAN_POINT('',(-10.,5.,19.));
#765=LINE('',#764,#763);
#766=EDGE_CURVE('E645',#225,#485,#765,.T.);
#767=ORIENTED_EDGE('',*,*,#766,.F.);
#768=ORIENTED_EDGE('',*,*,#226,.F.);
#769=DIRECTION('',(0.,-1.,0.));
#770=VECTOR('',#769,1.);
#771=CARTESIAN_POINT('',(-10.,20.,12.65));
#772=LINE('',#771,#770);
#773=CARTESIAN_POINT('',(-10.,20.,12.65));
#774=VERTEX_POINT('',#773);
#775=EDGE_CURVE('E651',#774,#217,#772,.T.);
#776=ORIENTED_EDGE('',*,*,#775,.F.);
#777=DIRECTION('',(0.,0.,1.));
#778=VECTOR('',#777,1.);
#779=CARTESIAN_POINT('',(-10.,20.,7.35));
#780=LINE('',#779,#778);
#781=CARTESIAN_POINT('',(-10.,20.,7.35));
#782=VERTEX_POINT('',#781);
#783=EDGE_CURVE('E658',#782,#774,#780,.T.);
#784=ORIENTED_EDGE('',*,*,#783,.F.);
#785=DIRECTION('',(0.,-1.,0.));
#786=VECTOR('',#785,1.);
#787=CARTESIAN_POINT('',(-10.,20.,7.35));
#788=LINE('',#787,#786);
#789=EDGE_CURVE('E665',#782,#72,#788,.T.);
#790=ORIENTED_EDGE('',*,*,#789,.T.);
#791=ORIENTED_EDGE('',*,*,#73,.F.);
#792=DIRECTION('',(0.,-1.,0.));
#793=VECTOR('',#792,1.);
#794=CARTESIAN_POINT('',(-10.,5.,1.));
#795=LINE('',#794,#793);
#796=EDGE_CURVE('E671',#64,#495,#795,.T.);
#797=ORIENTED_EDGE('',*,*,#796,.T.);
#798=EDGE_LOOP('',(#761,#767,#768,#776,#784,#790,#791,#797));
#799=FACE_BOUND('',#798,.T.);
#800=CARTESIAN_POINT('',(-10.,14.,10.));
#801=DIRECTION('',(1.,0.,0.));
#802=DIRECTION('',(0.,0.,-1.));
#803=AXIS2_PLACEMENT_3D('',#800,#801,#802);
#804=CIRCLE('',#803,2.);
#805=CARTESIAN_POINT('',(-10.,14.,8.));
#806=VERTEX_POINT('',#805);
#807=EDGE_CURVE('E675',#806,#806,#804,.T.);
#808=ORIENTED_EDGE('',*,*,#807,.T.);
#809=EDGE_LOOP('',(#808));
#810=FACE_BOUND('',#809,.T.);
#811=ADVANCED_FACE('F679',(#799,#810),#760,.F.);
#812=CARTESIAN_POINT('',(-9.0000000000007,5.,19.0000000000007));
#813=DIRECTION('',(0.,-1.,0.));
#814=DIRECTION('',(0.,0.,-1.));
#815=AXIS2_PLACEMENT_3D('',#812,#813,#814);
#816=CYLINDRICAL_SURFACE('',#815,0.999999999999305);
#817=ORIENTED_EDGE('',*,*,#488,.T.);
#818=ORIENTED_EDGE('',*,*,#751,.F.);
#819=ORIENTED_EDGE('',*,*,#235,.F.);
#820=ORIENTED_EDGE('',*,*,#766,.T.);
#821=EDGE_LOOP('',(#817,#818,#819,#820));
#822=FACE_BOUND('',#821,.T.);
#823=ADVANCED_FACE('F691',(#822),#816,.T.);
#824=CARTESIAN_POINT('',(-9.,5.,1.00000000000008));
#825=DIRECTION('',(0.,-1.,0.));
#826=DIRECTION('',(0.,0.,-1.));
#827=AXIS2_PLACEMENT_3D('',#824,#825,#826);
#828=CYLINDRICAL_SURFACE('',#827,1.00000000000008);
#829=ORIENTED_EDGE('',*,*,#505,.T.);
#830=ORIENTED_EDGE('',*,*,#796,.F.);
#831=ORIENTED_EDGE('',*,*,#65,.F.);
#832=ORIENTED_EDGE('',*,*,#674,.T.);
#833=EDGE_LOOP('',(#829,#830,#831,#832));
#834=FACE_BOUND('',#833,.T.);
#835=ADVANCED_FACE('F703',(#834),#828,.T.);
#836=CARTESIAN_POINT('',(4.5,2.,23.));
#837=DIRECTION('',(1.,0.,0.));
#838=DIRECTION('',(0.,0.,-1.));
#839=AXIS2_PLACEMENT_3D('',#836,#837,#838);
#840=PLANE('',#839);
#841=ORIENTED_EDGE('',*,*,#634,.F.);
#842=DIRECTION('',(0.,0.,1.));
#843=VECTOR('',#842,1.);
#844=CARTESIAN_POINT('',(4.5,2.,23.));
#845=LINE('',#844,#843);
#846=CARTESIAN_POINT('',(4.5,2.,23.));
#847=VERTEX_POINT('',#846);
#848=EDGE_CURVE('E713',#847,#625,#845,.T.);
#849=ORIENTED_EDGE('',*,*,#848,.F.);
#850=DIRECTION('',(0.,1.,0.));
#851=VECTOR('',#850,1.);
#852=CARTESIAN_POINT('',(4.5,2.,23.));
#853=LINE('',#852,#851);
#854=CARTESIAN_POINT('',(4.5,3.5,23.));
#855=VERTEX_POINT('',#854);
#856=EDGE_CURVE('E720',#847,#855,#853,.T.);
#857=ORIENTED_EDGE('',*,*,#856,.T.);
#858=DIRECTION('',(0.,0.,1.));
#859=VECTOR('',#858,1.);
#860=CARTESIAN_POINT('',(4.5,3.5,23.));
#861=LINE('',#860,#859);
#862=EDGE_CURVE('E727',#855,#633,#861,.T.);
#863=ORIENTED_EDGE('',*,*,#862,.T.);
#864=EDGE_LOOP('',(#841,#849,#857,#863));
#865=FACE_BOUND('',#864,.T.);
#866=ADVANCED_FACE('F731',(#865),#840,.T.);
#867=CARTESIAN_POINT('',(0.,0.,23.));
#868=DIRECTION('',(0.,0.,1.));
#869=DIRECTION('',(1.,0.,0.));
#870=AXIS2_PLACEMENT_3D('',#867,#868,#869);
#871=PLANE('',#870);
#872=DIRECTION('',(1.,0.,0.));
#873=VECTOR('',#872,1.);
#874=CARTESIAN_POINT('',(2.65,2.,23.));
#875=LINE('',#874,#873);
#876=EDGE_CURVE('E740',#410,#847,#875,.T.);
#877=ORIENTED_EDGE('',*,*,#876,.F.);
#878=ORIENTED_EDGE('',*,*,#413,.T.);
#879=DIRECTION('',(-1.,0.,0.));
#880=VECTOR('',#879,1.);
#881=CARTESIAN_POINT('',(4.5,3.5,23.));
#882=LINE('',#881,#880);
#883=EDGE_CURVE('E746',#855,#412,#882,.T.);
#884=ORIENTED_EDGE('',*,*,#883,.F.);
#885=ORIENTED_EDGE('',*,*,#856,.F.);
#886=EDGE_LOOP('',(#877,#878,#884,#885));
#887=FACE_BOUND('',#886,.T.);
#888=ADVANCED_FACE('F751',(#887),#871,.F.);
#889=CARTESIAN_POINT('',(4.5,3.5,23.));
#890=DIRECTION('',(0.,1.,0.));
#891=DIRECTION('',(0.,0.,1.));
#892=AXIS2_PLACEMENT_3D('',#889,#890,#891);
#893=PLANE('',#892);
#894=ORIENTED_EDGE('',*,*,#458,.F.);
#895=ORIENTED_EDGE('',*,*,#640,.F.);
#896=ORIENTED_EDGE('',*,*,#862,.F.);
#897=ORIENTED_EDGE('',*,*,#883,.T.);
#898=EDGE_LOOP('',(#894,#895,#896,#897));
#899=FACE_BOUND('',#898,.T.);
#900=ADVANCED_FACE('F763',(#899),#893,.T.);
#901=CARTESIAN_POINT('',(-4.5,2.,23.));
#902=DIRECTION('',(0.,-1.,0.));
#903=DIRECTION('',(0.,0.,-1.));
#904=AXIS2_PLACEMENT_3D('',#901,#902,#903);
#905=PLANE('',#904);
#906=ORIENTED_EDGE('',*,*,#421,.F.);
#907=ORIENTED_EDGE('',*,*,#876,.T.);
#908=ORIENTED_EDGE('',*,*,#848,.T.);
#909=ORIENTED_EDGE('',*,*,#626,.F.);
#910=EDGE_LOOP('',(#906,#907,#908,#909));
#911=FACE_BOUND('',#910,.T.);
#912=ADVANCED_FACE('F775',(#911),#905,.T.);
#913=DIRECTION('',(-1.,0.,0.));
#914=VECTOR('',#913,1.);
#915=CARTESIAN_POINT('',(-2.65,3.5,23.));
#916=LINE('',#915,#914);
#917=CARTESIAN_POINT('',(-4.5,3.5,23.));
#918=VERTEX_POINT('',#917);
#919=EDGE_CURVE('E784',#365,#918,#916,.T.);
#920=ORIENTED_EDGE('',*,*,#919,.F.);
#921=ORIENTED_EDGE('',*,*,#366,.T.);
#922=DIRECTION('',(1.,0.,0.));
#923=VECTOR('',#922,1.);
#924=CARTESIAN_POINT('',(-4.5,2.,23.));
#925=LINE('',#924,#923);
#926=CARTESIAN_POINT('',(-4.5,2.,23.));
#927=VERTEX_POINT('',#926);
#928=EDGE_CURVE('E790',#927,#357,#925,.T.);
#929=ORIENTED_EDGE('',*,*,#928,.F.);
#930=DIRECTION('',(0.,-1.,0.));
#931=VECTOR('',#930,1.);
#932=CARTESIAN_POINT('',(-4.5,3.5,23.));
#933=LINE('',#932,#931);
#934=EDGE_CURVE('E797',#918,#927,#933,.T.);
#935=ORIENTED_EDGE('',*,*,#934,.F.);
#936=EDGE_LOOP('',(#920,#921,#929,#935));
#937=FACE_BOUND('',#936,.T.);
#938=ADVANCED_FACE('F802',(#937),#871,.F.);
#939=ORIENTED_EDGE('',*,*,#358,.F.);
#940=ORIENTED_EDGE('',*,*,#615,.F.);
#941=DIRECTION('',(0.,0.,1.));
#942=VECTOR('',#941,1.);
#943=CARTESIAN_POINT('',(-4.5,2.,23.));
#944=LINE('',#943,#942);
#945=EDGE_CURVE('E813',#927,#608,#944,.T.);
#946=ORIENTED_EDGE('',*,*,#945,.F.);
#947=ORIENTED_EDGE('',*,*,#928,.T.);
#948=EDGE_LOOP('',(#939,#940,#946,#947));
#949=FACE_BOUND('',#948,.T.);
#950=ADVANCED_FACE('F817',(#949),#905,.T.);
#951=ORIENTED_EDGE('',*,*,#374,.F.);
#952=ORIENTED_EDGE('',*,*,#919,.T.);
#953=DIRECTION('',(0.,0.,1.));
#954=VECTOR('',#953,1.);
#955=CARTESIAN_POINT('',(-4.5,3.5,23.));
#956=LINE('',#955,#954);
#957=EDGE_CURVE('E828',#918,#600,#956,.T.);
#958=ORIENTED_EDGE('',*,*,#957,.T.);
#959=ORIENTED_EDGE('',*,*,#601,.F.);
#960=EDGE_LOOP('',(#951,#952,#958,#959));
#961=FACE_BOUND('',#960,.T.);
#962=ADVANCED_FACE('F832',(#961),#893,.T.);
#963=CARTESIAN_POINT('',(-4.5,3.5,23.));
#964=DIRECTION('',(-1.,0.,0.));
#965=DIRECTION('',(0.,0.,1.));
#966=AXIS2_PLACEMENT_3D('',#963,#964,#965);
#967=PLANE('',#966);
#968=ORIENTED_EDGE('',*,*,#609,.F.);
#969=ORIENTED_EDGE('',*,*,#957,.F.);
#970=ORIENTED_EDGE('',*,*,#934,.T.);
#971=ORIENTED_EDGE('',*,*,#945,.T.);
#972=EDGE_LOOP('',(#968,#969,#970,#971));
#973=FACE_BOUND('',#972,.T.);
#974=ADVANCED_FACE('F844',(#973),#967,.T.);
#975=CARTESIAN_POINT('',(-2.65,20.,5.));
#976=DIRECTION('',(0.,0.,-1.));
#977=DIRECTION('',(-1.,0.,0.));
#978=AXIS2_PLACEMENT_3D('',#975,#976,#977);
#979=PLANE('',#978);
#980=CARTESIAN_POINT('',(0.,14.,5.));
#981=DIRECTION('',(0.,0.,-1.));
#982=DIRECTION('',(-1.,0.,0.));
#983=AXIS2_PLACEMENT_3D('',#980,#981,#982);
#984=CIRCLE('',#983,2.);
#985=CARTESIAN_POINT('',(-2.,14.,5.));
#986=VERTEX_POINT('',#985);
#987=EDGE_CURVE('E851',#986,#986,#984,.T.);
#988=ORIENTED_EDGE('',*,*,#987,.T.);
#989=EDGE_LOOP('',(#988));
#990=FACE_BOUND('',#989,.T.);
#991=DIRECTION('',(0.,-1.,0.));
#992=VECTOR('',#991,1.);
#993=CARTESIAN_POINT('',(-2.65,20.,5.));
#994=LINE('',#993,#992);
#995=CARTESIAN_POINT('',(-2.65,20.,5.));
#996=VERTEX_POINT('',#995);
#997=EDGE_CURVE('E857',#996,#39,#994,.T.);
#998=ORIENTED_EDGE('',*,*,#997,.T.);
#999=ORIENTED_EDGE('',*,*,#40,.T.);
#1000=DIRECTION('',(0.,1.,0.));
#1001=VECTOR('',#1000,1.);
#1002=CARTESIAN_POINT('',(-5.,4.,5.));
#1003=LINE('',#1002,#1001);
#1004=CARTESIAN_POINT('',(-5.,4.,5.));
#1005=VERTEX_POINT('',#1004);
#1006=EDGE_CURVE('E863',#1005,#29,#1003,.T.);
#1007=ORIENTED_EDGE('',*,*,#1006,.F.);
#1008=DIRECTION('',(-1.,0.,0.));
#1009=VECTOR('',#1008,1.);
#1010=CARTESIAN_POINT('',(5.,4.,5.));
#1011=LINE('',#1010,#1009);
#1012=CARTESIAN_POINT('',(5.,4.,5.));
#1013=VERTEX_POINT('',#1012);
#1014=EDGE_CURVE('E870',#1013,#1005,#1011,.T.);
#1015=ORIENTED_EDGE('',*,*,#1014,.F.);
#1016=DIRECTION('',(0.,1.,0.));
#1017=VECTOR('',#1016,1.);
#1018=CARTESIAN_POINT('',(5.,4.,5.));
#1019=LINE('',#1018,#1017);
#1020=EDGE_CURVE('E877',#1013,#185,#1019,.T.);
#1021=ORIENTED_EDGE('',*,*,#1020,.T.);
#1022=ORIENTED_EDGE('',*,*,#186,.T.);
#1023=DIRECTION('',(0.,-1.,0.));
#1024=VECTOR('',#1023,1.);
#1025=CARTESIAN_POINT('',(2.65,20.,5.));
#1026=LINE('',#1025,#1024);
#1027=CARTESIAN_POINT('',(2.65,20.,5.));
#1028=VERTEX_POINT('',#1027);
#1029=EDGE_CURVE('E883',#1028,#175,#1026,.T.);
#1030=ORIENTED_EDGE('',*,*,#1029,.F.);
#1031=DIRECTION('',(1.,0.,0.));
#1032=VECTOR('',#1031,1.);
#1033=CARTESIAN_POINT('',(-2.65,20.,5.));
#1034=LINE('',#1033,#1032);
#1035=EDGE_CURVE('E890',#996,#1028,#1034,.T.);
#1036=ORIENTED_EDGE('',*,*,#1035,.F.);
#1037=EDGE_LOOP('',(#998,#999,#1007,#1015,#1021,#1022,#1030,#1036));
#1038=FACE_BOUND('',#1037,.T.);
#1039=ADVANCED_FACE('F896',(#990,#1038),#979,.F.);
#1040=CARTESIAN_POINT('',(-2.65,20.,0.));
#1041=DIRECTION('',(1.,0.,0.));
#1042=DIRECTION('',(0.,0.,-1.));
#1043=AXIS2_PLACEMENT_3D('',#1040,#1041,#1042);
#1044=PLANE('',#1043);
#1045=DIRECTION('',(0.,0.,1.));
#1046=VECTOR('',#1045,1.);
#1047=CARTESIAN_POINT('',(-2.65,20.,3.5));
#1048=LINE('',#1047,#1046);
#1049=CARTESIAN_POINT('',(-2.65,20.,3.5));
#1050=VERTEX_POINT('',#1049);
#1051=EDGE_CURVE('E905',#1050,#996,#1048,.T.);
#1052=ORIENTED_EDGE('',*,*,#1051,.F.);
#1053=DIRECTION('',(0.,-1.,0.));
#1054=VECTOR('',#1053,1.);
#1055=CARTESIAN_POINT('',(-2.65,20.,3.5));
#1056=LINE('',#1055,#1054);
#1057=CARTESIAN_POINT('',(-2.65,8.,3.5));
#1058=VERTEX_POINT('',#1057);
#1059=EDGE_CURVE('E912',#1050,#1058,#1056,.T.);
#1060=ORIENTED_EDGE('',*,*,#1059,.T.);
#1061=DIRECTION('',(0.,0.,1.));
#1062=VECTOR('',#1061,1.);
#1063=CARTESIAN_POINT('',(-2.65,8.,2.));
#1064=LINE('',#1063,#1062);
#1065=CARTESIAN_POINT('',(-2.65,8.,2.));
#1066=VERTEX_POINT('',#1065);
#1067=EDGE_CURVE('E919',#1066,#1058,#1064,.T.);
#1068=ORIENTED_EDGE('',*,*,#1067,.F.);
#1069=DIRECTION('',(0.,1.,0.));
#1070=VECTOR('',#1069,1.);
#1071=CARTESIAN_POINT('',(-2.65,8.,2.));
#1072=LINE('',#1071,#1070);
#1073=CARTESIAN_POINT('',(-2.65,20.,2.));
#1074=VERTEX_POINT('',#1073);
#1075=EDGE_CURVE('E926',#1066,#1074,#1072,.T.);
#1076=ORIENTED_EDGE('',*,*,#1075,.T.);
#1077=DIRECTION('',(0.,0.,1.));
#1078=VECTOR('',#1077,1.);
#1079=CARTESIAN_POINT('',(-2.65,20.,0.));
#1080=LINE('',#1079,#1078);
#1081=EDGE_CURVE('E933',#682,#1074,#1080,.T.);
#1082=ORIENTED_EDGE('',*,*,#1081,.F.);
#1083=ORIENTED_EDGE('',*,*,#683,.T.);
#1084=ORIENTED_EDGE('',*,*,#48,.T.);
#1085=ORIENTED_EDGE('',*,*,#997,.F.);
#1086=EDGE_LOOP('',(#1052,#1060,#1068,#1076,#1082,#1083,#1084,#1085));
#1087=FACE_BOUND('',#1086,.T.);
#1088=ADVANCED_FACE('F940',(#1087),#1044,.F.);
#1089=CARTESIAN_POINT('',(2.65,20.,5.));
#1090=DIRECTION('',(-1.,0.,0.));
#1091=DIRECTION('',(0.,0.,1.));
#1092=AXIS2_PLACEMENT_3D('',#1089,#1090,#1091);
#1093=PLANE('',#1092);
#1094=DIRECTION('',(0.,0.,-1.));
#1095=VECTOR('',#1094,1.);
#1096=CARTESIAN_POINT('',(2.65,8.,3.5));
#1097=LINE('',#1096,#1095);
#1098=CARTESIAN_POINT('',(2.65,8.,3.5));
#1099=VERTEX_POINT('',#1098);
#1100=CARTESIAN_POINT('',(2.65,8.,2.));
#1101=VERTEX_POINT('',#1100);
#1102=EDGE_CURVE('E949',#1099,#1101,#1097,.T.);
#1103=ORIENTED_EDGE('',*,*,#1102,.F.);
#1104=DIRECTION('',(0.,1.,0.));
#1105=VECTOR('',#1104,1.);
#1106=CARTESIAN_POINT('',(2.65,8.,3.5));
#1107=LINE('',#1106,#1105);
#1108=CARTESIAN_POINT('',(2.65,20.,3.5));
#1109=VERTEX_POINT('',#1108);
#1110=EDGE_CURVE('E956',#1099,#1109,#1107,.T.);
#1111=ORIENTED_EDGE('',*,*,#1110,.T.);
#1112=DIRECTION('',(0.,0.,-1.));
#1113=VECTOR('',#1112,1.);
#1114=CARTESIAN_POINT('',(2.65,20.,5.));
#1115=LINE('',#1114,#1113);
#1116=EDGE_CURVE('E963',#1028,#1109,#1115,.T.);
#1117=ORIENTED_EDGE('',*,*,#1116,.F.);
#1118=ORIENTED_EDGE('',*,*,#1029,.T.);
#1119=ORIENTED_EDGE('',*,*,#178,.T.);
#1120=ORIENTED_EDGE('',*,*,#697,.F.);
#1121=DIRECTION('',(0.,0.,-1.));
#1122=VECTOR('',#1121,1.);
#1123=CARTESIAN_POINT('',(2.65,20.,2.));
#1124=LINE('',#1123,#1122);
#1125=CARTESIAN_POINT('',(2.65,20.,2.));
#1126=VERTEX_POINT('',#1125);
#1127=EDGE_CURVE('E971',#1126,#690,#1124,.T.);
#1128=ORIENTED_EDGE('',*,*,#1127,.F.);
#1129=DIRECTION('',(0.,-1.,0.));
#1130=VECTOR('',#1129,1.);
#1131=CARTESIAN_POINT('',(2.65,20.,2.));
#1132=LINE('',#1131,#1130);
#1133=EDGE_CURVE('E978',#1126,#1101,#1132,.T.);
#1134=ORIENTED_EDGE('',*,*,#1133,.T.);
#1135=EDGE_LOOP('',(#1103,#1111,#1117,#1118,#1119,#1120,#1128,#1134));
#1136=FACE_BOUND('',#1135,.T.);
#1137=ADVANCED_FACE('F984',(#1136),#1093,.F.);
#1138=CARTESIAN_POINT('',(0.,20.,0.));
#1139=DIRECTION('',(0.,1.,0.));
#1140=DIRECTION('',(0.,0.,1.));
#1141=AXIS2_PLACEMENT_3D('',#1138,#1139,#1140);
#1142=PLANE('',#1141);
#1143=ORIENTED_EDGE('',*,*,#1081,.T.);
#1144=DIRECTION('',(-1.,0.,0.));
#1145=VECTOR('',#1144,1.);
#1146=CARTESIAN_POINT('',(-2.65,20.,2.));
#1147=LINE('',#1146,#1145);
#1148=CARTESIAN_POINT('',(-4.5,20.,2.));
#1149=VERTEX_POINT('',#1148);
#1150=EDGE_CURVE('E994',#1074,#1149,#1147,.T.);
#1151=ORIENTED_EDGE('',*,*,#1150,.T.);
#1152=DIRECTION('',(0.,0.,1.));
#1153=VECTOR('',#1152,1.);
#1154=CARTESIAN_POINT('',(-4.5,20.,2.));
#1155=LINE('',#1154,#1153);
#1156=CARTESIAN_POINT('',(-4.5,20.,3.5));
#1157=VERTEX_POINT('',#1156);
#1158=EDGE_CURVE('E1001',#1149,#1157,#1155,.T.);
#1159=ORIENTED_EDGE('',*,*,#1158,.T.);
#1160=DIRECTION('',(1.,0.,0.));
#1161=VECTOR('',#1160,1.);
#1162=CARTESIAN_POINT('',(-4.5,20.,3.5));
#1163=LINE('',#1162,#1161);
#1164=EDGE_CURVE('E1008',#1157,#1050,#1163,.T.);
#1165=ORIENTED_EDGE('',*,*,#1164,.T.);
#1166=ORIENTED_EDGE('',*,*,#1051,.T.);
#1167=ORIENTED_EDGE('',*,*,#1035,.T.);
#1168=ORIENTED_EDGE('',*,*,#1116,.T.);
#1169=DIRECTION('',(1.,0.,0.));
#1170=VECTOR('',#1169,1.);
#1171=CARTESIAN_POINT('',(2.65,20.,3.5));
#1172=LINE('',#1171,#1170);
#1173=CARTESIAN_POINT('',(4.5,20.,3.5));
#1174=VERTEX_POINT('',#1173);
#1175=EDGE_CURVE('E1016',#1109,#1174,#1172,.T.);
#1176=ORIENTED_EDGE('',*,*,#1175,.T.);
#1177=DIRECTION('',(0.,0.,-1.));
#1178=VECTOR('',#1177,1.);
#1179=CARTESIAN_POINT('',(4.5,20.,3.5));
#1180=LINE('',#1179,#1178);
#1181=CARTESIAN_POINT('',(4.5,20.,2.));
#1182=VERTEX_POINT('',#1181);
#1183=EDGE_CURVE('E1023',#1174,#1182,#1180,.T.);
#1184=ORIENTED_EDGE('',*,*,#1183,.T.);
#1185=DIRECTION('',(-1.,0.,0.));
#1186=VECTOR('',#1185,1.);
#1187=CARTESIAN_POINT('',(4.5,20.,2.));
#1188=LINE('',#1187,#1186);
#1189=EDGE_CURVE('E1030',#1182,#1126,#1188,.T.);
#1190=ORIENTED_EDGE('',*,*,#1189,.T.);
#1191=ORIENTED_EDGE('',*,*,#1127,.T.);
#1192=ORIENTED_EDGE('',*,*,#691,.T.);
#1193=EDGE_LOOP('',(#1143,#1151,#1159,#1165,#1166,#1167,#1168,#1176,#1184,#1190,#1191,#1192));
#1194=FACE_BOUND('',#1193,.T.);
#1195=ADVANCED_FACE('F1036',(#1194),#1142,.T.);
#1196=CARTESIAN_POINT('',(4.5,8.,3.5));
#1197=DIRECTION('',(1.,0.,0.));
#1198=DIRECTION('',(0.,0.,-1.));
#1199=AXIS2_PLACEMENT_3D('',#1196,#1197,#1198);
#1200=PLANE('',#1199);
#1201=ORIENTED_EDGE('',*,*,#1183,.F.);
#1202=DIRECTION('',(0.,1.,0.));
#1203=VECTOR('',#1202,1.);
#1204=CARTESIAN_POINT('',(4.5,8.,3.5));
#1205=LINE('',#1204,#1203);
#1206=CARTESIAN_POINT('',(4.5,8.,3.5));
#1207=VERTEX_POINT('',#1206);
#1208=EDGE_CURVE('E1046',#1207,#1174,#1205,.T.);
#1209=ORIENTED_EDGE('',*,*,#1208,.F.);
#1210=DIRECTION('',(0.,0.,-1.));
#1211=VECTOR('',#1210,1.);
#1212=CARTESIAN_POINT('',(4.5,8.,3.5));
#1213=LINE('',#1212,#1211);
#1214=CARTESIAN_POINT('',(4.5,8.,2.));
#1215=VERTEX_POINT('',#1214);
#1216=EDGE_CURVE('E1053',#1207,#1215,#1213,.T.);
#1217=ORIENTED_EDGE('',*,*,#1216,.T.);
#1218=DIRECTION('',(0.,1.,0.));
#1219=VECTOR('',#1218,1.);
#1220=CARTESIAN_POINT('',(4.5,8.,2.));
#1221=LINE('',#1220,#1219);
#1222=EDGE_CURVE('E1060',#1215,#1182,#1221,.T.);
#1223=ORIENTED_EDGE('',*,*,#1222,.T.);
#1224=EDGE_LOOP('',(#1201,#1209,#1217,#1223));
#1225=FACE_BOUND('',#1224,.T.);
#1226=ADVANCED_FACE('F1064',(#1225),#1200,.T.);
#1227=CARTESIAN_POINT('',(0.,8.,0.));
#1228=DIRECTION('',(0.,1.,0.));
#1229=DIRECTION('',(0.,0.,1.));
#1230=AXIS2_PLACEMENT_3D('',#1227,#1228,#1229);
#1231=PLANE('',#1230);
#1232=DIRECTION('',(1.,0.,0.));
#1233=VECTOR('',#1232,1.);
#1234=CARTESIAN_POINT('',(2.65,8.,3.5));
#1235=LINE('',#1234,#1233);
#1236=EDGE_CURVE('E1073',#1099,#1207,#1235,.T.);
#1237=ORIENTED_EDGE('',*,*,#1236,.F.);
#1238=ORIENTED_EDGE('',*,*,#1102,.T.);
#1239=DIRECTION('',(-1.,0.,0.));
#1240=VECTOR('',#1239,1.);
#1241=CARTESIAN_POINT('',(4.5,8.,2.));
#1242=LINE('',#1241,#1240);
#1243=EDGE_CURVE('E1079',#1215,#1101,#1242,.T.);
#1244=ORIENTED_EDGE('',*,*,#1243,.F.);
#1245=ORIENTED_EDGE('',*,*,#1216,.F.);
#1246=EDGE_LOOP('',(#1237,#1238,#1244,#1245));
#1247=FACE_BOUND('',#1246,.T.);
#1248=ADVANCED_FACE('F1084',(#1247),#1231,.F.);
#1249=CARTESIAN_POINT('',(4.5,8.,2.));
#1250=DIRECTION('',(0.,0.,-1.));
#1251=DIRECTION('',(-1.,0.,0.));
#1252=AXIS2_PLACEMENT_3D('',#1249,#1250,#1251);
#1253=PLANE('',#1252);
#1254=ORIENTED_EDGE('',*,*,#1133,.F.);
#1255=ORIENTED_EDGE('',*,*,#1189,.F.);
#1256=ORIENTED_EDGE('',*,*,#1222,.F.);
#1257=ORIENTED_EDGE('',*,*,#1243,.T.);
#1258=EDGE_LOOP('',(#1254,#1255,#1256,#1257));
#1259=FACE_BOUND('',#1258,.T.);
#1260=ADVANCED_FACE('F1096',(#1259),#1253,.T.);
#1261=CARTESIAN_POINT('',(-4.5,8.,3.5));
#1262=DIRECTION('',(0.,0.,1.));
#1263=DIRECTION('',(1.,0.,0.));
#1264=AXIS2_PLACEMENT_3D('',#1261,#1262,#1263);
#1265=PLANE('',#1264);
#1266=ORIENTED_EDGE('',*,*,#1110,.F.);
#1267=ORIENTED_EDGE('',*,*,#1236,.T.);
#1268=ORIENTED_EDGE('',*,*,#1208,.T.);
#1269=ORIENTED_EDGE('',*,*,#1175,.F.);
#1270=EDGE_LOOP('',(#1266,#1267,#1268,#1269));
#1271=FACE_BOUND('',#1270,.T.);
#1272=ADVANCED_FACE('F1108',(#1271),#1265,.T.);
#1273=DIRECTION('',(-1.,0.,0.));
#1274=VECTOR('',#1273,1.);
#1275=CARTESIAN_POINT('',(-2.65,8.,2.));
#1276=LINE('',#1275,#1274);
#1277=CARTESIAN_POINT('',(-4.5,8.,2.));
#1278=VERTEX_POINT('',#1277);
#1279=EDGE_CURVE('E1117',#1066,#1278,#1276,.T.);
#1280=ORIENTED_EDGE('',*,*,#1279,.F.);
#1281=ORIENTED_EDGE('',*,*,#1067,.T.);
#1282=DIRECTION('',(1.,0.,0.));
#1283=VECTOR('',#1282,1.);
#1284=CARTESIAN_POINT('',(-4.5,8.,3.5));
#1285=LINE('',#1284,#1283);
#1286=CARTESIAN_POINT('',(-4.5,8.,3.5));
#1287=VERTEX_POINT('',#1286);
#1288=EDGE_CURVE('E1123',#1287,#1058,#1285,.T.);
#1289=ORIENTED_EDGE('',*,*,#1288,.F.);
#1290=DIRECTION('',(0.,0.,1.));
#1291=VECTOR('',#1290,1.);
#1292=CARTESIAN_POINT('',(-4.5,8.,2.));
#1293=LINE('',#1292,#1291);
#1294=EDGE_CURVE('E1130',#1278,#1287,#1293,.T.);
#1295=ORIENTED_EDGE('',*,*,#1294,.F.);
#1296=EDGE_LOOP('',(#1280,#1281,#1289,#1295));
#1297=FACE_BOUND('',#1296,.T.);
#1298=ADVANCED_FACE('F1135',(#1297),#1231,.F.);
#1299=ORIENTED_EDGE('',*,*,#1059,.F.);
#1300=ORIENTED_EDGE('',*,*,#1164,.F.);
#1301=DIRECTION('',(0.,1.,0.));
#1302=VECTOR('',#1301,1.);
#1303=CARTESIAN_POINT('',(-4.5,8.,3.5));
#1304=LINE('',#1303,#1302);
#1305=EDGE_CURVE('E1146',#1287,#1157,#1304,.T.);
#1306=ORIENTED_EDGE('',*,*,#1305,.F.);
#1307=ORIENTED_EDGE('',*,*,#1288,.T.);
#1308=EDGE_LOOP('',(#1299,#1300,#1306,#1307));
#1309=FACE_BOUND('',#1308,.T.);
#1310=ADVANCED_FACE('F1150',(#1309),#1265,.T.);
#1311=ORIENTED_EDGE('',*,*,#1075,.F.);
#1312=ORIENTED_EDGE('',*,*,#1279,.T.);
#1313=DIRECTION('',(0.,1.,0.));
#1314=VECTOR('',#1313,1.);
#1315=CARTESIAN_POINT('',(-4.5,8.,2.));
#1316=LINE('',#1315,#1314);
#1317=EDGE_CURVE('E1161',#1278,#1149,#1316,.T.);
#1318=ORIENTED_EDGE('',*,*,#1317,.T.);
#1319=ORIENTED_EDGE('',*,*,#1150,.F.);
#1320=EDGE_LOOP('',(#1311,#1312,#1318,#1319));
#1321=FACE_BOUND('',#1320,.T.);
#1322=ADVANCED_FACE('F1165',(#1321),#1253,.T.);
#1323=CARTESIAN_POINT('',(-4.5,8.,2.));
#1324=DIRECTION('',(-1.,0.,0.));
#1325=DIRECTION('',(0.,0.,1.));
#1326=AXIS2_PLACEMENT_3D('',#1323,#1324,#1325);
#1327=PLANE('',#1326);
#1328=ORIENTED_EDGE('',*,*,#1158,.F.);
#1329=ORIENTED_EDGE('',*,*,#1317,.F.);
#1330=ORIENTED_EDGE('',*,*,#1294,.T.);
#1331=ORIENTED_EDGE('',*,*,#1305,.T.);
#1332=EDGE_LOOP('',(#1328,#1329,#1330,#1331));
#1333=FACE_BOUND('',#1332,.T.);
#1334=ADVANCED_FACE('F1177',(#1333),#1327,.T.);
#1335=CARTESIAN_POINT('',(0.,0.,29.));
#1336=DIRECTION('',(0.,-1.,0.));
#1337=DIRECTION('',(0.,0.,-1.));
#1338=AXIS2_PLACEMENT_3D('',#1335,#1336,#1337);
#1339=CONICAL_SURFACE('',#1338,2.,0.785398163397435);
#1340=CARTESIAN_POINT('',(0.,0.37900000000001,29.));
#1341=DIRECTION('',(0.,1.,0.));
#1342=DIRECTION('',(0.,0.,1.));
#1343=AXIS2_PLACEMENT_3D('',#1340,#1341,#1342);
#1344=CIRCLE('',#1343,1.621);
#1345=CARTESIAN_POINT('',(0.,0.37900000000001,30.621));
#1346=VERTEX_POINT('',#1345);
#1347=EDGE_CURVE('E1184',#1346,#1346,#1344,.T.);
#1348=ORIENTED_EDGE('',*,*,#1347,.T.);
#1349=EDGE_LOOP('',(#1348));
#1350=FACE_BOUND('',#1349,.T.);
#1351=ORIENTED_EDGE('',*,*,#584,.F.);
#1352=EDGE_LOOP('',(#1351));
#1353=FACE_BOUND('',#1352,.T.);
#1354=ADVANCED_FACE('F1190',(#1350,#1353),#1339,.F.);
#1355=CARTESIAN_POINT('',(0.,5.,29.));
#1356=DIRECTION('',(0.,1.,0.));
#1357=DIRECTION('',(0.,0.,1.));
#1358=AXIS2_PLACEMENT_3D('',#1355,#1356,#1357);
#1359=CYLINDRICAL_SURFACE('',#1358,1.621);
#1360=CARTESIAN_POINT('',(0.,4.621,29.));
#1361=DIRECTION('',(0.,1.,0.));
#1362=DIRECTION('',(0.,0.,1.));
#1363=AXIS2_PLACEMENT_3D('',#1360,#1361,#1362);
#1364=CIRCLE('',#1363,1.621);
#1365=CARTESIAN_POINT('',(0.,4.621,30.621));
#1366=VERTEX_POINT('',#1365);
#1367=EDGE_CURVE('E1197',#1366,#1366,#1364,.T.);
#1368=ORIENTED_EDGE('',*,*,#1367,.T.);
#1369=EDGE_LOOP('',(#1368));
#1370=FACE_BOUND('',#1369,.T.);
#1371=ORIENTED_EDGE('',*,*,#1347,.F.);
#1372=EDGE_LOOP('',(#1371));
#1373=FACE_BOUND('',#1372,.T.);
#1374=ADVANCED_FACE('F1203',(#1370,#1373),#1359,.F.);
#1375=CARTESIAN_POINT('',(0.,4.621,29.));
#1376=DIRECTION('',(0.,1.,0.));
#1377=DIRECTION('',(0.,0.,1.));
#1378=AXIS2_PLACEMENT_3D('',#1375,#1376,#1377);
#1379=CONICAL_SURFACE('',#1378,1.621,0.785398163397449);
#1380=ORIENTED_EDGE('',*,*,#332,.T.);
#1381=EDGE_LOOP('',(#1380));
#1382=FACE_BOUND('',#1381,.T.);
#1383=ORIENTED_EDGE('',*,*,#1367,.F.);
#1384=EDGE_LOOP('',(#1383));
#1385=FACE_BOUND('',#1384,.T.);
#1386=ADVANCED_FACE('F1214',(#1382,#1385),#1379,.F.);
#1387=CARTESIAN_POINT('',(0.,14.,5.));
#1388=DIRECTION('',(0.,0.,1.));
#1389=DIRECTION('',(1.,0.,0.));
#1390=AXIS2_PLACEMENT_3D('',#1387,#1388,#1389);
#1391=CONICAL_SURFACE('',#1390,2.,0.785398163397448);
#1392=CARTESIAN_POINT('',(0.,14.,4.621));
#1393=DIRECTION('',(0.,0.,-1.));
#1394=DIRECTION('',(-1.,0.,0.));
#1395=AXIS2_PLACEMENT_3D('',#1392,#1393,#1394);
#1396=CIRCLE('',#1395,1.621);
#1397=CARTESIAN_POINT('',(-1.621,14.,4.621));
#1398=VERTEX_POINT('',#1397);
#1399=EDGE_CURVE('E1221',#1398,#1398,#1396,.T.);
#1400=ORIENTED_EDGE('',*,*,#1399,.T.);
#1401=EDGE_LOOP('',(#1400));
#1402=FACE_BOUND('',#1401,.T.);
#1403=ORIENTED_EDGE('',*,*,#987,.F.);
#1404=EDGE_LOOP('',(#1403));
#1405=FACE_BOUND('',#1404,.T.);
#1406=ADVANCED_FACE('F1227',(#1402,#1405),#1391,.F.);
#1407=CARTESIAN_POINT('',(0.,14.,0.));
#1408=DIRECTION('',(0.,0.,-1.));
#1409=DIRECTION('',(-1.,0.,0.));
#1410=AXIS2_PLACEMENT_3D('',#1407,#1408,#1409);
#1411=CYLINDRICAL_SURFACE('',#1410,1.621);
#1412=CARTESIAN_POINT('',(0.,14.,0.379));
#1413=DIRECTION('',(0.,0.,-1.));
#1414=DIRECTION('',(-1.,0.,0.));
#1415=AXIS2_PLACEMENT_3D('',#1412,#1413,#1414);
#1416=CIRCLE('',#1415,1.621);
#1417=CARTESIAN_POINT('',(-1.621,14.,0.379));
#1418=VERTEX_POINT('',#1417);
#1419=EDGE_CURVE('E1234',#1418,#1418,#1416,.T.);
#1420=ORIENTED_EDGE('',*,*,#1419,.T.);
#1421=EDGE_LOOP('',(#1420));
#1422=FACE_BOUND('',#1421,.T.);
#1423=ORIENTED_EDGE('',*,*,#1399,.F.);
#1424=EDGE_LOOP('',(#1423));
#1425=FACE_BOUND('',#1424,.T.);
#1426=ADVANCED_FACE('F1240',(#1422,#1425),#1411,.F.);
#1427=CARTESIAN_POINT('',(0.,14.,0.379));
#1428=DIRECTION('',(0.,0.,-1.));
#1429=DIRECTION('',(-1.,0.,0.));
#1430=AXIS2_PLACEMENT_3D('',#1427,#1428,#1429);
#1431=CONICAL_SURFACE('',#1430,1.621,0.785398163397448);
#1432=ORIENTED_EDGE('',*,*,#659,.T.);
#1433=EDGE_LOOP('',(#1432));
#1434=FACE_BOUND('',#1433,.T.);
#1435=ORIENTED_EDGE('',*,*,#1419,.F.);
#1436=EDGE_LOOP('',(#1435));
#1437=FACE_BOUND('',#1436,.T.);
#1438=ADVANCED_FACE('F1251',(#1434,#1437),#1431,.F.);
#1439=CARTESIAN_POINT('',(-5.,20.,12.65));
#1440=DIRECTION('',(-1.,0.,0.));
#1441=DIRECTION('',(0.,0.,1.));
#1442=AXIS2_PLACEMENT_3D('',#1439,#1440,#1441);
#1443=PLANE('',#1442);
#1444=CARTESIAN_POINT('',(-5.,14.,10.));
#1445=DIRECTION('',(1.,0.,0.));
#1446=DIRECTION('',(0.,0.,-1.));
#1447=AXIS2_PLACEMENT_3D('',#1444,#1445,#1446);
#1448=CIRCLE('',#1447,2.);
#1449=CARTESIAN_POINT('',(-5.,14.,8.));
#1450=VERTEX_POINT('',#1449);
#1451=EDGE_CURVE('E1258',#1450,#1450,#1448,.T.);
#1452=ORIENTED_EDGE('',*,*,#1451,.F.);
#1453=EDGE_LOOP('',(#1452));
#1454=FACE_BOUND('',#1453,.T.);
#1455=DIRECTION('',(0.,-1.,0.));
#1456=VECTOR('',#1455,1.);
#1457=CARTESIAN_POINT('',(-5.,20.,12.65));
#1458=LINE('',#1457,#1456);
#1459=CARTESIAN_POINT('',(-5.,20.,12.65));
#1460=VERTEX_POINT('',#1459);
#1461=EDGE_CURVE('E1264',#1460,#209,#1458,.T.);
#1462=ORIENTED_EDGE('',*,*,#1461,.T.);
#1463=ORIENTED_EDGE('',*,*,#210,.T.);
#1464=DIRECTION('',(0.,1.,0.));
#1465=VECTOR('',#1464,1.);
#1466=CARTESIAN_POINT('',(-5.,4.,15.));
#1467=LINE('',#1466,#1465);
#1468=CARTESIAN_POINT('',(-5.,4.,15.));
#1469=VERTEX_POINT('',#1468);
#1470=EDGE_CURVE('E1270',#1469,#201,#1467,.T.);
#1471=ORIENTED_EDGE('',*,*,#1470,.F.);
#1472=DIRECTION('',(0.,0.,1.));
#1473=VECTOR('',#1472,1.);
#1474=CARTESIAN_POINT('',(-5.,4.,5.));
#1475=LINE('',#1474,#1473);
#1476=EDGE_CURVE('E1277',#1005,#1469,#1475,.T.);
#1477=ORIENTED_EDGE('',*,*,#1476,.F.);
#1478=ORIENTED_EDGE('',*,*,#1006,.T.);
#1479=ORIENTED_EDGE('',*,*,#32,.T.);
#1480=DIRECTION('',(0.,-1.,0.));
#1481=VECTOR('',#1480,1.);
#1482=CARTESIAN_POINT('',(-5.,20.,7.35));
#1483=LINE('',#1482,#1481);
#1484=CARTESIAN_POINT('',(-5.,20.,7.35));
#1485=VERTEX_POINT('',#1484);
#1486=EDGE_CURVE('E1284',#1485,#31,#1483,.T.);
#1487=ORIENTED_EDGE('',*,*,#1486,.F.);
#1488=DIRECTION('',(0.,0.,-1.));
#1489=VECTOR('',#1488,1.);
#1490=CARTESIAN_POINT('',(-5.,20.,12.65));
#1491=LINE('',#1490,#1489);
#1492=EDGE_CURVE('E1291',#1460,#1485,#1491,.T.);
#1493=ORIENTED_EDGE('',*,*,#1492,.F.);
#1494=EDGE_LOOP('',(#1462,#1463,#1471,#1477,#1478,#1479,#1487,#1493));
#1495=FACE_BOUND('',#1494,.T.);
#1496=ADVANCED_FACE('F1297',(#1454,#1495),#1443,.F.);
#1497=CARTESIAN_POINT('',(-10.,20.,12.65));
#1498=DIRECTION('',(0.,0.,-1.));
#1499=DIRECTION('',(-1.,0.,0.));
#1500=AXIS2_PLACEMENT_3D('',#1497,#1498,#1499);
#1501=PLANE('',#1500);
#1502=DIRECTION('',(1.,0.,0.));
#1503=VECTOR('',#1502,1.);
#1504=CARTESIAN_POINT('',(-8.,8.,12.65));
#1505=LINE('',#1504,#1503);
#1506=CARTESIAN_POINT('',(-8.,8.,12.65));
#1507=VERTEX_POINT('',#1506);
#1508=CARTESIAN_POINT('',(-6.5,8.,12.65));
#1509=VERTEX_POINT('',#1508);
#1510=EDGE_CURVE('E1306',#1507,#1509,#1505,.T.);
#1511=ORIENTED_EDGE('',*,*,#1510,.F.);
#1512=DIRECTION('',(0.,1.,0.));
#1513=VECTOR('',#1512,1.);
#1514=CARTESIAN_POINT('',(-8.,8.,12.65));
#1515=LINE('',#1514,#1513);
#1516=CARTESIAN_POINT('',(-8.,20.,12.65));
#1517=VERTEX_POINT('',#1516);
#1518=EDGE_CURVE('E1313',#1507,#1517,#1515,.T.);
#1519=ORIENTED_EDGE('',*,*,#1518,.T.);
#1520=DIRECTION('',(1.,0.,0.));
#1521=VECTOR('',#1520,1.);
#1522=CARTESIAN_POINT('',(-10.,20.,12.65));
#1523=LINE('',#1522,#1521);
#1524=EDGE_CURVE('E1320',#774,#1517,#1523,.T.);
#1525=ORIENTED_EDGE('',*,*,#1524,.F.);
#1526=ORIENTED_EDGE('',*,*,#775,.T.);
#1527=ORIENTED_EDGE('',*,*,#218,.T.);
#1528=ORIENTED_EDGE('',*,*,#1461,.F.);
#1529=DIRECTION('',(1.,0.,0.));
#1530=VECTOR('',#1529,1.);
#1531=CARTESIAN_POINT('',(-6.5,20.,12.65));
#1532=LINE('',#1531,#1530);
#1533=CARTESIAN_POINT('',(-6.5,20.,12.65));
#1534=VERTEX_POINT('',#1533);
#1535=EDGE_CURVE('E1328',#1534,#1460,#1532,.T.);
#1536=ORIENTED_EDGE('',*,*,#1535,.F.);
#1537=DIRECTION('',(0.,-1.,0.));
#1538=VECTOR('',#1537,1.);
#1539=CARTESIAN_POINT('',(-6.5,20.,12.65));
#1540=LINE('',#1539,#1538);
#1541=EDGE_CURVE('E1335',#1534,#1509,#1540,.T.);
#1542=ORIENTED_EDGE('',*,*,#1541,.T.);
#1543=EDGE_LOOP('',(#1511,#1519,#1525,#1526,#1527,#1528,#1536,#1542));
#1544=FACE_BOUND('',#1543,.T.);
#1545=ADVANCED_FACE('F1341',(#1544),#1501,.F.);
#1546=CARTESIAN_POINT('',(-5.,20.,7.35));
#1547=DIRECTION('',(0.,0.,1.));
#1548=DIRECTION('',(1.,0.,0.));
#1549=AXIS2_PLACEMENT_3D('',#1546,#1547,#1548);
#1550=PLANE('',#1549);
#1551=DIRECTION('',(-1.,0.,0.));
#1552=VECTOR('',#1551,1.);
#1553=CARTESIAN_POINT('',(-8.,20.,7.35));
#1554=LINE('',#1553,#1552);
#1555=CARTESIAN_POINT('',(-8.,20.,7.35));
#1556=VERTEX_POINT('',#1555);
#1557=EDGE_CURVE('E1350',#1556,#782,#1554,.T.);
#1558=ORIENTED_EDGE('',*,*,#1557,.F.);
#1559=DIRECTION('',(0.,-1.,0.));
#1560=VECTOR('',#1559,1.);
#1561=CARTESIAN_POINT('',(-8.,20.,7.35));
#1562=LINE('',#1561,#1560);
#1563=CARTESIAN_POINT('',(-8.,8.,7.35));
#1564=VERTEX_POINT('',#1563);
#1565=EDGE_CURVE('E1357',#1556,#1564,#1562,.T.);
#1566=ORIENTED_EDGE('',*,*,#1565,.T.);
#1567=DIRECTION('',(-1.,0.,0.));
#1568=VECTOR('',#1567,1.);
#1569=CARTESIAN_POINT('',(-6.5,8.,7.35));
#1570=LINE('',#1569,#1568);
#1571=CARTESIAN_POINT('',(-6.5,8.,7.35));
#1572=VERTEX_POINT('',#1571);
#1573=EDGE_CURVE('E1364',#1572,#1564,#1570,.T.);
#1574=ORIENTED_EDGE('',*,*,#1573,.F.);
#1575=DIRECTION('',(0.,1.,0.));
#1576=VECTOR('',#1575,1.);
#1577=CARTESIAN_POINT('',(-6.5,8.,7.35));
#1578=LINE('',#1577,#1576);
#1579=CARTESIAN_POINT('',(-6.5,20.,7.35));
#1580=VERTEX_POINT('',#1579);
#1581=EDGE_CURVE('E1371',#1572,#1580,#1578,.T.);
#1582=ORIENTED_EDGE('',*,*,#1581,.T.);
#1583=DIRECTION('',(-1.,0.,0.));
#1584=VECTOR('',#1583,1.);
#1585=CARTESIAN_POINT('',(-5.,20.,7.35));
#1586=LINE('',#1585,#1584);
#1587=EDGE_CURVE('E1378',#1485,#1580,#1586,.T.);
#1588=ORIENTED_EDGE('',*,*,#1587,.F.);
#1589=ORIENTED_EDGE('',*,*,#1486,.T.);
#1590=ORIENTED_EDGE('',*,*,#79,.T.);
#1591=ORIENTED_EDGE('',*,*,#789,.F.);
#1592=EDGE_LOOP('',(#1558,#1566,#1574,#1582,#1588,#1589,#1590,#1591));
#1593=FACE_BOUND('',#1592,.T.);
#1594=ADVANCED_FACE('F1385',(#1593),#1550,.F.);
#1595=CARTESIAN_POINT('',(0.,20.,0.));
#1596=DIRECTION('',(0.,1.,0.));
#1597=DIRECTION('',(0.,0.,1.));
#1598=AXIS2_PLACEMENT_3D('',#1595,#1596,#1597);
#1599=PLANE('',#1598);
#1600=ORIENTED_EDGE('',*,*,#1587,.T.);
#1601=DIRECTION('',(0.,0.,-1.));
#1602=VECTOR('',#1601,1.);
#1603=CARTESIAN_POINT('',(-6.5,20.,7.35));
#1604=LINE('',#1603,#1602);
#1605=CARTESIAN_POINT('',(-6.5,20.,5.5));
#1606=VERTEX_POINT('',#1605);
#1607=EDGE_CURVE('E1395',#1580,#1606,#1604,.T.);
#1608=ORIENTED_EDGE('',*,*,#1607,.T.);
#1609=DIRECTION('',(-1.,0.,0.));
#1610=VECTOR('',#1609,1.);
#1611=CARTESIAN_POINT('',(-6.5,20.,5.5));
#1612=LINE('',#1611,#1610);
#1613=CARTESIAN_POINT('',(-8.,20.,5.5));
#1614=VERTEX_POINT('',#1613);
#1615=EDGE_CURVE('E1402',#1606,#1614,#1612,.T.);
#1616=ORIENTED_EDGE('',*,*,#1615,.T.);
#1617=DIRECTION('',(0.,0.,1.));
#1618=VECTOR('',#1617,1.);
#1619=CARTESIAN_POINT('',(-8.,20.,5.5));
#1620=LINE('',#1619,#1618);
#1621=EDGE_CURVE('E1409',#1614,#1556,#1620,.T.);
#1622=ORIENTED_EDGE('',*,*,#1621,.T.);
#1623=ORIENTED_EDGE('',*,*,#1557,.T.);
#1624=ORIENTED_EDGE('',*,*,#783,.T.);
#1625=ORIENTED_EDGE('',*,*,#1524,.T.);
#1626=DIRECTION('',(0.,0.,1.));
#1627=VECTOR('',#1626,1.);
#1628=CARTESIAN_POINT('',(-8.,20.,12.65));
#1629=LINE('',#1628,#1627);
#1630=CARTESIAN_POINT('',(-8.,20.,14.5));
#1631=VERTEX_POINT('',#1630);
#1632=EDGE_CURVE('E1417',#1517,#1631,#1629,.T.);
#1633=ORIENTED_EDGE('',*,*,#1632,.T.);
#1634=DIRECTION('',(1.,0.,0.));
#1635=VECTOR('',#1634,1.);
#1636=CARTESIAN_POINT('',(-8.,20.,14.5));
#1637=LINE('',#1636,#1635);
#1638=CARTESIAN_POINT('',(-6.5,20.,14.5));
#1639=VERTEX_POINT('',#1638);
#1640=EDGE_CURVE('E1424',#1631,#1639,#1637,.T.);
#1641=ORIENTED_EDGE('',*,*,#1640,.T.);
#1642=DIRECTION('',(0.,0.,-1.));
#1643=VECTOR('',#1642,1.);
#1644=CARTESIAN_POINT('',(-6.5,20.,14.5));
#1645=LINE('',#1644,#1643);
#1646=EDGE_CURVE('E1431',#1639,#1534,#1645,.T.);
#1647=ORIENTED_EDGE('',*,*,#1646,.T.);
#1648=ORIENTED_EDGE('',*,*,#1535,.T.);
#1649=ORIENTED_EDGE('',*,*,#1492,.T.);
#1650=EDGE_LOOP('',(#1600,#1608,#1616,#1622,#1623,#1624,#1625,#1633,#1641,#1647,#1648,#1649));
#1651=FACE_BOUND('',#1650,.T.);
#1652=ADVANCED_FACE('F1437',(#1651),#1599,.T.);
#1653=CARTESIAN_POINT('',(-6.5,8.,5.5));
#1654=DIRECTION('',(0.,0.,-1.));
#1655=DIRECTION('',(-1.,0.,0.));
#1656=AXIS2_PLACEMENT_3D('',#1653,#1654,#1655);
#1657=PLANE('',#1656);
#1658=ORIENTED_EDGE('',*,*,#1615,.F.);
#1659=DIRECTION('',(0.,1.,0.));
#1660=VECTOR('',#1659,1.);
#1661=CARTESIAN_POINT('',(-6.5,8.,5.5));
#1662=LINE('',#1661,#1660);
#1663=CARTESIAN_POINT('',(-6.5,8.,5.5));
#1664=VERTEX_POINT('',#1663);
#1665=EDGE_CURVE('E1447',#1664,#1606,#1662,.T.);
#1666=ORIENTED_EDGE('',*,*,#1665,.F.);
#1667=DIRECTION('',(-1.,0.,0.));
#1668=VECTOR('',#1667,1.);
#1669=CARTESIAN_POINT('',(-6.5,8.,5.5));
#1670=LINE('',#1669,#1668);
#1671=CARTESIAN_POINT('',(-8.,8.,5.5));
#1672=VERTEX_POINT('',#1671);
#1673=EDGE_CURVE('E1454',#1664,#1672,#1670,.T.);
#1674=ORIENTED_EDGE('',*,*,#1673,.T.);
#1675=DIRECTION('',(0.,1.,0.));
#1676=VECTOR('',#1675,1.);
#1677=CARTESIAN_POINT('',(-8.,8.,5.5));
#1678=LINE('',#1677,#1676);
#1679=EDGE_CURVE('E1461',#1672,#1614,#1678,.T.);
#1680=ORIENTED_EDGE('',*,*,#1679,.T.);
#1681=EDGE_LOOP('',(#1658,#1666,#1674,#1680));
#1682=FACE_BOUND('',#1681,.T.);
#1683=ADVANCED_FACE('F1465',(#1682),#1657,.T.);
#1684=CARTESIAN_POINT('',(0.,8.,0.));
#1685=DIRECTION('',(0.,1.,0.));
#1686=DIRECTION('',(0.,0.,1.));
#1687=AXIS2_PLACEMENT_3D('',#1684,#1685,#1686);
#1688=PLANE('',#1687);
#1689=DIRECTION('',(0.,0.,-1.));
#1690=VECTOR('',#1689,1.);
#1691=CARTESIAN_POINT('',(-6.5,8.,7.35));
#1692=LINE('',#1691,#1690);
#1693=EDGE_CURVE('E1474',#1572,#1664,#1692,.T.);
#1694=ORIENTED_EDGE('',*,*,#1693,.F.);
#1695=ORIENTED_EDGE('',*,*,#1573,.T.);
#1696=DIRECTION('',(0.,0.,1.));
#1697=VECTOR('',#1696,1.);
#1698=CARTESIAN_POINT('',(-8.,8.,5.5));
#1699=LINE('',#1698,#1697);
#1700=EDGE_CURVE('E1480',#1672,#1564,#1699,.T.);
#1701=ORIENTED_EDGE('',*,*,#1700,.F.);
#1702=ORIENTED_EDGE('',*,*,#1673,.F.);
#1703=EDGE_LOOP('',(#1694,#1695,#1701,#1702));
#1704=FACE_BOUND('',#1703,.T.);
#1705=ADVANCED_FACE('F1485',(#1704),#1688,.F.);
#1706=CARTESIAN_POINT('',(-6.5,8.,14.5));
#1707=DIRECTION('',(1.,0.,0.));
#1708=DIRECTION('',(0.,0.,-1.));
#1709=AXIS2_PLACEMENT_3D('',#1706,#1707,#1708);
#1710=PLANE('',#1709);
#1711=ORIENTED_EDGE('',*,*,#1581,.F.);
#1712=ORIENTED_EDGE('',*,*,#1693,.T.);
#1713=ORIENTED_EDGE('',*,*,#1665,.T.);
#1714=ORIENTED_EDGE('',*,*,#1607,.F.);
#1715=EDGE_LOOP('',(#1711,#1712,#1713,#1714));
#1716=FACE_BOUND('',#1715,.T.);
#1717=ADVANCED_FACE('F1497',(#1716),#1710,.T.);
#1718=CARTESIAN_POINT('',(-8.,8.,5.5));
#1719=DIRECTION('',(-1.,0.,0.));
#1720=DIRECTION('',(0.,0.,1.));
#1721=AXIS2_PLACEMENT_3D('',#1718,#1719,#1720);
#1722=PLANE('',#1721);
#1723=ORIENTED_EDGE('',*,*,#1565,.F.);
#1724=ORIENTED_EDGE('',*,*,#1621,.F.);
#1725=ORIENTED_EDGE('',*,*,#1679,.F.);
#1726=ORIENTED_EDGE('',*,*,#1700,.T.);
#1727=EDGE_LOOP('',(#1723,#1724,#1725,#1726));
#1728=FACE_BOUND('',#1727,.T.);
#1729=ADVANCED_FACE('F1509',(#1728),#1722,.T.);
#1730=DIRECTION('',(0.,0.,1.));
#1731=VECTOR('',#1730,1.);
#1732=CARTESIAN_POINT('',(-8.,8.,12.65));
#1733=LINE('',#1732,#1731);
#1734=CARTESIAN_POINT('',(-8.,8.,14.5));
#1735=VERTEX_POINT('',#1734);
#1736=EDGE_CURVE('E1518',#1507,#1735,#1733,.T.);
#1737=ORIENTED_EDGE('',*,*,#1736,.F.);
#1738=ORIENTED_EDGE('',*,*,#1510,.T.);
#1739=DIRECTION('',(0.,0.,-1.));
#1740=VECTOR('',#1739,1.);
#1741=CARTESIAN_POINT('',(-6.5,8.,14.5));
#1742=LINE('',#1741,#1740);
#1743=CARTESIAN_POINT('',(-6.5,8.,14.5));
#1744=VERTEX_POINT('',#1743);
#1745=EDGE_CURVE('E1524',#1744,#1509,#1742,.T.);
#1746=ORIENTED_EDGE('',*,*,#1745,.F.);
#1747=DIRECTION('',(1.,0.,0.));
#1748=VECTOR('',#1747,1.);
#1749=CARTESIAN_POINT('',(-8.,8.,14.5));
#1750=LINE('',#1749,#1748);
#1751=EDGE_CURVE('E1531',#1735,#1744,#1750,.T.);
#1752=ORIENTED_EDGE('',*,*,#1751,.F.);
#1753=EDGE_LOOP('',(#1737,#1738,#1746,#1752));
#1754=FACE_BOUND('',#1753,.T.);
#1755=ADVANCED_FACE('F1536',(#1754),#1688,.F.);
#1756=ORIENTED_EDGE('',*,*,#1518,.F.);
#1757=ORIENTED_EDGE('',*,*,#1736,.T.);
#1758=DIRECTION('',(0.,1.,0.));
#1759=VECTOR('',#1758,1.);
#1760=CARTESIAN_POINT('',(-8.,8.,14.5));
#1761=LINE('',#1760,#1759);
#1762=EDGE_CURVE('E1547',#1735,#1631,#1761,.T.);
#1763=ORIENTED_EDGE('',*,*,#1762,.T.);
#1764=ORIENTED_EDGE('',*,*,#1632,.F.);
#1765=EDGE_LOOP('',(#1756,#1757,#1763,#1764));
#1766=FACE_BOUND('',#1765,.T.);
#1767=ADVANCED_FACE('F1551',(#1766),#1722,.T.);
#1768=ORIENTED_EDGE('',*,*,#1541,.F.);
#1769=ORIENTED_EDGE('',*,*,#1646,.F.);
#1770=DIRECTION('',(0.,1.,0.));
#1771=VECTOR('',#1770,1.);
#1772=CARTESIAN_POINT('',(-6.5,8.,14.5));
#1773=LINE('',#1772,#1771);
#1774=EDGE_CURVE('E1562',#1744,#1639,#1773,.T.);
#1775=ORIENTED_EDGE('',*,*,#1774,.F.);
#1776=ORIENTED_EDGE('',*,*,#1745,.T.);
#1777=EDGE_LOOP('',(#1768,#1769,#1775,#1776));
#1778=FACE_BOUND('',#1777,.T.);
#1779=ADVANCED_FACE('F1566',(#1778),#1710,.T.);
#1780=CARTESIAN_POINT('',(-8.,8.,14.5));
#1781=DIRECTION('',(0.,0.,1.));
#1782=DIRECTION('',(1.,0.,0.));
#1783=AXIS2_PLACEMENT_3D('',#1780,#1781,#1782);
#1784=PLANE('',#1783);
#1785=ORIENTED_EDGE('',*,*,#1640,.F.);
#1786=ORIENTED_EDGE('',*,*,#1762,.F.);
#1787=ORIENTED_EDGE('',*,*,#1751,.T.);
#1788=ORIENTED_EDGE('',*,*,#1774,.T.);
#1789=EDGE_LOOP('',(#1785,#1786,#1787,#1788));
#1790=FACE_BOUND('',#1789,.T.);
#1791=ADVANCED_FACE('F1578',(#1790),#1784,.T.);
#1792=CARTESIAN_POINT('',(-10.,14.,10.));
#1793=DIRECTION('',(-1.,0.,0.));
#1794=DIRECTION('',(0.,0.,1.));
#1795=AXIS2_PLACEMENT_3D('',#1792,#1793,#1794);
#1796=CONICAL_SURFACE('',#1795,2.,0.785398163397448);
#1797=CARTESIAN_POINT('',(-9.621,14.,10.));
#1798=DIRECTION('',(1.,0.,0.));
#1799=DIRECTION('',(0.,0.,-1.));
#1800=AXIS2_PLACEMENT_3D('',#1797,#1798,#1799);
#1801=CIRCLE('',#1800,1.621);
#1802=CARTESIAN_POINT('',(-9.621,14.,8.379));
#1803=VERTEX_POINT('',#1802);
#1804=EDGE_CURVE('E1585',#1803,#1803,#1801,.T.);
#1805=ORIENTED_EDGE('',*,*,#1804,.T.);
#1806=EDGE_LOOP('',(#1805));
#1807=FACE_BOUND('',#1806,.T.);
#1808=ORIENTED_EDGE('',*,*,#807,.F.);
#1809=EDGE_LOOP('',(#1808));
#1810=FACE_BOUND('',#1809,.T.);
#1811=ADVANCED_FACE('F1591',(#1807,#1810),#1796,.F.);
#1812=CARTESIAN_POINT('',(-5.,14.,10.));
#1813=DIRECTION('',(1.,0.,0.));
#1814=DIRECTION('',(0.,0.,-1.));
#1815=AXIS2_PLACEMENT_3D('',#1812,#1813,#1814);
#1816=CYLINDRICAL_SURFACE('',#1815,1.621);
#1817=CARTESIAN_POINT('',(-5.379,14.,10.));
#1818=DIRECTION('',(1.,0.,0.));
#1819=DIRECTION('',(0.,0.,-1.));
#1820=AXIS2_PLACEMENT_3D('',#1817,#1818,#1819);
#1821=CIRCLE('',#1820,1.621);
#1822=CARTESIAN_POINT('',(-5.379,14.,8.379));
#1823=VERTEX_POINT('',#1822);
#1824=EDGE_CURVE('E1598',#1823,#1823,#1821,.T.);
#1825=ORIENTED_EDGE('',*,*,#1824,.T.);
#1826=EDGE_LOOP('',(#1825));
#1827=FACE_BOUND('',#1826,.T.);
#1828=ORIENTED_EDGE('',*,*,#1804,.F.);
#1829=EDGE_LOOP('',(#1828));
#1830=FACE_BOUND('',#1829,.T.);
#1831=ADVANCED_FACE('F1604',(#1827,#1830),#1816,.F.);
#1832=CARTESIAN_POINT('',(-5.379,14.,10.));
#1833=DIRECTION('',(1.,0.,0.));
#1834=DIRECTION('',(0.,0.,-1.));
#1835=AXIS2_PLACEMENT_3D('',#1832,#1833,#1834);
#1836=CONICAL_SURFACE('',#1835,1.621,0.785398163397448);
#1837=ORIENTED_EDGE('',*,*,#1451,.T.);
#1838=EDGE_LOOP('',(#1837));
#1839=FACE_BOUND('',#1838,.T.);
#1840=ORIENTED_EDGE('',*,*,#1824,.F.);
#1841=EDGE_LOOP('',(#1840));
#1842=FACE_BOUND('',#1841,.T.);
#1843=ADVANCED_FACE('F1615',(#1839,#1842),#1836,.F.);
#1844=CARTESIAN_POINT('',(25.,5.,12.65));
#1845=DIRECTION('',(0.,0.,-1.));
#1846=DIRECTION('',(-1.,0.,0.));
#1847=AXIS2_PLACEMENT_3D('',#1844,#1845,#1846);
#1848=PLANE('',#1847);
#1849=DIRECTION('',(0.,-1.,0.));
#1850=VECTOR('',#1849,1.);
#1851=CARTESIAN_POINT('',(13.,3.5,12.65));
#1852=LINE('',#1851,#1850);
#1853=CARTESIAN_POINT('',(13.,3.5,12.65));
#1854=VERTEX_POINT('',#1853);
#1855=CARTESIAN_POINT('',(13.,2.,12.65));
#1856=VERTEX_POINT('',#1855);
#1857=EDGE_CURVE('E1624',#1854,#1856,#1852,.T.);
#1858=ORIENTED_EDGE('',*,*,#1857,.F.);
#1859=DIRECTION('',(1.,0.,0.));
#1860=VECTOR('',#1859,1.);
#1861=CARTESIAN_POINT('',(13.,3.5,12.65));
#1862=LINE('',#1861,#1860);
#1863=CARTESIAN_POINT('',(25.,3.5,12.65));
#1864=VERTEX_POINT('',#1863);
#1865=EDGE_CURVE('E1631',#1854,#1864,#1862,.T.);
#1866=ORIENTED_EDGE('',*,*,#1865,.T.);
#1867=DIRECTION('',(0.,-1.,0.));
#1868=VECTOR('',#1867,1.);
#1869=CARTESIAN_POINT('',(25.,5.,12.65));
#1870=LINE('',#1869,#1868);
#1871=EDGE_CURVE('E1638',#290,#1864,#1870,.T.);
#1872=ORIENTED_EDGE('',*,*,#1871,.F.);
#1873=ORIENTED_EDGE('',*,*,#291,.T.);
#1874=ORIENTED_EDGE('',*,*,#97,.T.);
#1875=ORIENTED_EDGE('',*,*,#543,.F.);
#1876=DIRECTION('',(0.,-1.,0.));
#1877=VECTOR('',#1876,1.);
#1878=CARTESIAN_POINT('',(25.,2.,12.65));
#1879=LINE('',#1878,#1877);
#1880=CARTESIAN_POINT('',(25.,2.,12.65));
#1881=VERTEX_POINT('',#1880);
#1882=EDGE_CURVE('E1646',#1881,#536,#1879,.T.);
#1883=ORIENTED_EDGE('',*,*,#1882,.F.);
#1884=DIRECTION('',(-1.,0.,0.));
#1885=VECTOR('',#1884,1.);
#1886=CARTESIAN_POINT('',(25.,2.,12.65));
#1887=LINE('',#1886,#1885);
#1888=EDGE_CURVE('E1653',#1881,#1856,#1887,.T.);
#1889=ORIENTED_EDGE('',*,*,#1888,.T.);
#1890=EDGE_LOOP('',(#1858,#1866,#1872,#1873,#1874,#1875,#1883,#1889));
#1891=FACE_BOUND('',#1890,.T.);
#1892=ADVANCED_FACE('F1659',(#1891),#1848,.F.);
#1893=CARTESIAN_POINT('',(25.,0.,7.35));
#1894=DIRECTION('',(0.,0.,1.));
#1895=DIRECTION('',(1.,0.,0.));
#1896=AXIS2_PLACEMENT_3D('',#1893,#1894,#1895);
#1897=PLANE('',#1896);
#1898=DIRECTION('',(0.,1.,0.));
#1899=VECTOR('',#1898,1.);
#1900=CARTESIAN_POINT('',(25.,3.5,7.35));
#1901=LINE('',#1900,#1899);
#1902=CARTESIAN_POINT('',(25.,3.5,7.35));
#1903=VERTEX_POINT('',#1902);
#1904=EDGE_CURVE('E1668',#1903,#298,#1901,.T.);
#1905=ORIENTED_EDGE('',*,*,#1904,.F.);
#1906=DIRECTION('',(-1.,0.,0.));
#1907=VECTOR('',#1906,1.);
#1908=CARTESIAN_POINT('',(25.,3.5,7.35));
#1909=LINE('',#1908,#1907);
#1910=CARTESIAN_POINT('',(13.,3.5,7.35));
#1911=VERTEX_POINT('',#1910);
#1912=EDGE_CURVE('E1675',#1903,#1911,#1909,.T.);
#1913=ORIENTED_EDGE('',*,*,#1912,.T.);
#1914=DIRECTION('',(0.,1.,0.));
#1915=VECTOR('',#1914,1.);
#1916=CARTESIAN_POINT('',(13.,2.,7.35));
#1917=LINE('',#1916,#1915);
#1918=CARTESIAN_POINT('',(13.,2.,7.35));
#1919=VERTEX_POINT('',#1918);
#1920=EDGE_CURVE('E1682',#1919,#1911,#1917,.T.);
#1921=ORIENTED_EDGE('',*,*,#1920,.F.);
#1922=DIRECTION('',(1.,0.,0.));
#1923=VECTOR('',#1922,1.);
#1924=CARTESIAN_POINT('',(13.,2.,7.35));
#1925=LINE('',#1924,#1923);
#1926=CARTESIAN_POINT('',(25.,2.,7.35));
#1927=VERTEX_POINT('',#1926);
#1928=EDGE_CURVE('E1689',#1919,#1927,#1925,.T.);
#1929=ORIENTED_EDGE('',*,*,#1928,.T.);
#1930=DIRECTION('',(0.,1.,0.));
#1931=VECTOR('',#1930,1.);
#1932=CARTESIAN_POINT('',(25.,0.,7.35));
#1933=LINE('',#1932,#1931);
#1934=EDGE_CURVE('E1696',#528,#1927,#1933,.T.);
#1935=ORIENTED_EDGE('',*,*,#1934,.F.);
#1936=ORIENTED_EDGE('',*,*,#529,.T.);
#1937=ORIENTED_EDGE('',*,*,#132,.T.);
#1938=ORIENTED_EDGE('',*,*,#305,.F.);
#1939=EDGE_LOOP('',(#1905,#1913,#1921,#1929,#1935,#1936,#1937,#1938));
#1940=FACE_BOUND('',#1939,.T.);
#1941=ADVANCED_FACE('F1703',(#1940),#1897,.F.);
#1942=CARTESIAN_POINT('',(25.,0.,0.));
#1943=DIRECTION('',(1.,0.,0.));
#1944=DIRECTION('',(0.,0.,-1.));
#1945=AXIS2_PLACEMENT_3D('',#1942,#1943,#1944);
#1946=PLANE('',#1945);
#1947=ORIENTED_EDGE('',*,*,#1934,.T.);
#1948=DIRECTION('',(0.,0.,-1.));
#1949=VECTOR('',#1948,1.);
#1950=CARTESIAN_POINT('',(25.,2.,7.35));
#1951=LINE('',#1950,#1949);
#1952=CARTESIAN_POINT('',(25.,2.,5.5));
#1953=VERTEX_POINT('',#1952);
#1954=EDGE_CURVE('E1713',#1927,#1953,#1951,.T.);
#1955=ORIENTED_EDGE('',*,*,#1954,.T.);
#1956=DIRECTION('',(0.,1.,0.));
#1957=VECTOR('',#1956,1.);
#1958=CARTESIAN_POINT('',(25.,2.,5.5));
#1959=LINE('',#1958,#1957);
#1960=CARTESIAN_POINT('',(25.,3.5,5.5));
#1961=VERTEX_POINT('',#1960);
#1962=EDGE_CURVE('E1720',#1953,#1961,#1959,.T.);
#1963=ORIENTED_EDGE('',*,*,#1962,.T.);
#1964=DIRECTION('',(0.,0.,1.));
#1965=VECTOR('',#1964,1.);
#1966=CARTESIAN_POINT('',(25.,3.5,5.5));
#1967=LINE('',#1966,#1965);
#1968=EDGE_CURVE('E1727',#1961,#1903,#1967,.T.);
#1969=ORIENTED_EDGE('',*,*,#1968,.T.);
#1970=ORIENTED_EDGE('',*,*,#1904,.T.);
#1971=ORIENTED_EDGE('',*,*,#299,.T.);
#1972=ORIENTED_EDGE('',*,*,#1871,.T.);
#1973=DIRECTION('',(0.,0.,1.));
#1974=VECTOR('',#1973,1.);
#1975=CARTESIAN_POINT('',(25.,3.5,12.65));
#1976=LINE('',#1975,#1974);
#1977=CARTESIAN_POINT('',(25.,3.5,14.5));
#1978=VERTEX_POINT('',#1977);
#1979=EDGE_CURVE('E1735',#1864,#1978,#1976,.T.);
#1980=ORIENTED_EDGE('',*,*,#1979,.T.);
#1981=DIRECTION('',(0.,-1.,0.));
#1982=VECTOR('',#1981,1.);
#1983=CARTESIAN_POINT('',(25.,3.5,14.5));
#1984=LINE('',#1983,#1982);
#1985=CARTESIAN_POINT('',(25.,2.,14.5));
#1986=VERTEX_POINT('',#1985);
#1987=EDGE_CURVE('E1742',#1978,#1986,#1984,.T.);
#1988=ORIENTED_EDGE('',*,*,#1987,.T.);
#1989=DIRECTION('',(0.,0.,-1.));
#1990=VECTOR('',#1989,1.);
#1991=CARTESIAN_POINT('',(25.,2.,14.5));
#1992=LINE('',#1991,#1990);
#1993=EDGE_CURVE('E1749',#1986,#1881,#1992,.T.);
#1994=ORIENTED_EDGE('',*,*,#1993,.T.);
#1995=ORIENTED_EDGE('',*,*,#1882,.T.);
#1996=ORIENTED_EDGE('',*,*,#537,.T.);
#1997=EDGE_LOOP('',(#1947,#1955,#1963,#1969,#1970,#1971,#1972,#1980,#1988,#1994,#1995,#1996));
#1998=FACE_BOUND('',#1997,.T.);
#1999=ADVANCED_FACE('F1755',(#1998),#1946,.T.);
#2000=CARTESIAN_POINT('',(-5.,4.,15.));
#2001=DIRECTION('',(0.,0.,1.));
#2002=DIRECTION('',(1.,0.,0.));
#2003=AXIS2_PLACEMENT_3D('',#2000,#2001,#2002);
#2004=PLANE('',#2003);
#2005=ORIENTED_EDGE('',*,*,#202,.T.);
#2006=DIRECTION('',(0.,1.,0.));
#2007=VECTOR('',#2006,1.);
#2008=CARTESIAN_POINT('',(5.,4.,15.));
#2009=LINE('',#2008,#2007);
#2010=CARTESIAN_POINT('',(5.,4.,15.));
#2011=VERTEX_POINT('',#2010);
#2012=EDGE_CURVE('E1765',#2011,#193,#2009,.T.);
#2013=ORIENTED_EDGE('',*,*,#2012,.F.);
#2014=DIRECTION('',(1.,0.,0.));
#2015=VECTOR('',#2014,1.);
#2016=CARTESIAN_POINT('',(-5.,4.,15.));
#2017=LINE('',#2016,#2015);
#2018=EDGE_CURVE('E1772',#1469,#2011,#2017,.T.);
#2019=ORIENTED_EDGE('',*,*,#2018,.F.);
#2020=ORIENTED_EDGE('',*,*,#1470,.T.);
#2021=EDGE_LOOP('',(#2005,#2013,#2019,#2020));
#2022=FACE_BOUND('',#2021,.T.);
#2023=ADVANCED_FACE('F1777',(#2022),#2004,.F.);
#2024=CARTESIAN_POINT('',(5.,4.,15.));
#2025=DIRECTION('',(1.,0.,0.));
#2026=DIRECTION('',(0.,0.,-1.));
#2027=AXIS2_PLACEMENT_3D('',#2024,#2025,#2026);
#2028=PLANE('',#2027);
#2029=ORIENTED_EDGE('',*,*,#194,.T.);
#2030=ORIENTED_EDGE('',*,*,#1020,.F.);
#2031=DIRECTION('',(0.,0.,-1.));
#2032=VECTOR('',#2031,1.);
#2033=CARTESIAN_POINT('',(5.,4.,15.));
#2034=LINE('',#2033,#2032);
#2035=EDGE_CURVE('E1788',#2011,#1013,#2034,.T.);
#2036=ORIENTED_EDGE('',*,*,#2035,.F.);
#2037=ORIENTED_EDGE('',*,*,#2012,.T.);
#2038=EDGE_LOOP('',(#2029,#2030,#2036,#2037));
#2039=FACE_BOUND('',#2038,.T.);
#2040=ADVANCED_FACE('F1793',(#2039),#2028,.F.);
#2041=CARTESIAN_POINT('',(0.,4.,0.));
#2042=DIRECTION('',(0.,1.,0.));
#2043=DIRECTION('',(0.,0.,1.));
#2044=AXIS2_PLACEMENT_3D('',#2041,#2042,#2043);
#2045=PLANE('',#2044);
#2046=ORIENTED_EDGE('',*,*,#1014,.T.);
#2047=ORIENTED_EDGE('',*,*,#1476,.T.);
#2048=ORIENTED_EDGE('',*,*,#2018,.T.);
#2049=ORIENTED_EDGE('',*,*,#2035,.T.);
#2050=EDGE_LOOP('',(#2046,#2047,#2048,#2049));
#2051=FACE_BOUND('',#2050,.T.);
#2052=ADVANCED_FACE('F1805',(#2051),#2045,.T.);
#2053=CARTESIAN_POINT('',(13.,2.,5.5));
#2054=DIRECTION('',(0.,0.,-1.));
#2055=DIRECTION('',(-1.,0.,0.));
#2056=AXIS2_PLACEMENT_3D('',#2053,#2054,#2055);
#2057=PLANE('',#2056);
#2058=ORIENTED_EDGE('',*,*,#1962,.F.);
#2059=DIRECTION('',(1.,0.,0.));
#2060=VECTOR('',#2059,1.);
#2061=CARTESIAN_POINT('',(13.,2.,5.5));
#2062=LINE('',#2061,#2060);
#2063=CARTESIAN_POINT('',(13.,2.,5.5));
#2064=VERTEX_POINT('',#2063);
#2065=EDGE_CURVE('E1815',#2064,#1953,#2062,.T.);
#2066=ORIENTED_EDGE('',*,*,#2065,.F.);
#2067=DIRECTION('',(0.,1.,0.));
#2068=VECTOR('',#2067,1.);
#2069=CARTESIAN_POINT('',(13.,2.,5.5));
#2070=LINE('',#2069,#2068);
#2071=CARTESIAN_POINT('',(13.,3.5,5.5));
#2072=VERTEX_POINT('',#2071);
#2073=EDGE_CURVE('E1822',#2064,#2072,#2070,.T.);
#2074=ORIENTED_EDGE('',*,*,#2073,.T.);
#2075=DIRECTION('',(1.,0.,0.));
#2076=VECTOR('',#2075,1.);
#2077=CARTESIAN_POINT('',(13.,3.5,5.5));
#2078=LINE('',#2077,#2076);
#2079=EDGE_CURVE('E1829',#2072,#1961,#2078,.T.);
#2080=ORIENTED_EDGE('',*,*,#2079,.T.);
#2081=EDGE_LOOP('',(#2058,#2066,#2074,#2080));
#2082=FACE_BOUND('',#2081,.T.);
#2083=ADVANCED_FACE('F1833',(#2082),#2057,.T.);
#2084=CARTESIAN_POINT('',(13.,0.,0.));
#2085=DIRECTION('',(1.,0.,0.));
#2086=DIRECTION('',(0.,0.,-1.));
#2087=AXIS2_PLACEMENT_3D('',#2084,#2085,#2086);
#2088=PLANE('',#2087);
#2089=DIRECTION('',(0.,0.,-1.));
#2090=VECTOR('',#2089,1.);
#2091=CARTESIAN_POINT('',(13.,2.,7.35));
#2092=LINE('',#2091,#2090);
#2093=EDGE_CURVE('E1842',#1919,#2064,#2092,.T.);
#2094=ORIENTED_EDGE('',*,*,#2093,.F.);
#2095=ORIENTED_EDGE('',*,*,#1920,.T.);
#2096=DIRECTION('',(0.,0.,1.));
#2097=VECTOR('',#2096,1.);
#2098=CARTESIAN_POINT('',(13.,3.5,5.5));
#2099=LINE('',#2098,#2097);
#2100=EDGE_CURVE('E1848',#2072,#1911,#2099,.T.);
#2101=ORIENTED_EDGE('',*,*,#2100,.F.);
#2102=ORIENTED_EDGE('',*,*,#2073,.F.);
#2103=EDGE_LOOP('',(#2094,#2095,#2101,#2102));
#2104=FACE_BOUND('',#2103,.T.);
#2105=ADVANCED_FACE('F1853',(#2104),#2088,.F.);
#2106=CARTESIAN_POINT('',(13.,2.,14.5));
#2107=DIRECTION('',(0.,-1.,0.));
#2108=DIRECTION('',(0.,0.,-1.));
#2109=AXIS2_PLACEMENT_3D('',#2106,#2107,#2108);
#2110=PLANE('',#2109);
#2111=ORIENTED_EDGE('',*,*,#1928,.F.);
#2112=ORIENTED_EDGE('',*,*,#2093,.T.);
#2113=ORIENTED_EDGE('',*,*,#2065,.T.);
#2114=ORIENTED_EDGE('',*,*,#1954,.F.);
#2115=EDGE_LOOP('',(#2111,#2112,#2113,#2114));
#2116=FACE_BOUND('',#2115,.T.);
#2117=ADVANCED_FACE('F1865',(#2116),#2110,.T.);
#2118=CARTESIAN_POINT('',(13.,3.5,5.5));
#2119=DIRECTION('',(0.,1.,0.));
#2120=DIRECTION('',(0.,0.,1.));
#2121=AXIS2_PLACEMENT_3D('',#2118,#2119,#2120);
#2122=PLANE('',#2121);
#2123=ORIENTED_EDGE('',*,*,#1912,.F.);
#2124=ORIENTED_EDGE('',*,*,#1968,.F.);
#2125=ORIENTED_EDGE('',*,*,#2079,.F.);
#2126=ORIENTED_EDGE('',*,*,#2100,.T.);
#2127=EDGE_LOOP('',(#2123,#2124,#2125,#2126));
#2128=FACE_BOUND('',#2127,.T.);
#2129=ADVANCED_FACE('F1877',(#2128),#2122,.T.);
#2130=DIRECTION('',(0.,0.,1.));
#2131=VECTOR('',#2130,1.);
#2132=CARTESIAN_POINT('',(13.,3.5,12.65));
#2133=LINE('',#2132,#2131);
#2134=CARTESIAN_POINT('',(13.,3.5,14.5));
#2135=VERTEX_POINT('',#2134);
#2136=EDGE_CURVE('E1886',#1854,#2135,#2133,.T.);
#2137=ORIENTED_EDGE('',*,*,#2136,.F.);
#2138=ORIENTED_EDGE('',*,*,#1857,.T.);
#2139=DIRECTION('',(0.,0.,-1.));
#2140=VECTOR('',#2139,1.);
#2141=CARTESIAN_POINT('',(13.,2.,14.5));
#2142=LINE('',#2141,#2140);
#2143=CARTESIAN_POINT('',(13.,2.,14.5));
#2144=VERTEX_POINT('',#2143);
#2145=EDGE_CURVE('E1892',#2144,#1856,#2142,.T.);
#2146=ORIENTED_EDGE('',*,*,#2145,.F.);
#2147=DIRECTION('',(0.,-1.,0.));
#2148=VECTOR('',#2147,1.);
#2149=CARTESIAN_POINT('',(13.,3.5,14.5));
#2150=LINE('',#2149,#2148);
#2151=EDGE_CURVE('E1899',#2135,#2144,#2150,.T.);
#2152=ORIENTED_EDGE('',*,*,#2151,.F.);
#2153=EDGE_LOOP('',(#2137,#2138,#2146,#2152));
#2154=FACE_BOUND('',#2153,.T.);
#2155=ADVANCED_FACE('F1904',(#2154),#2088,.F.);
#2156=ORIENTED_EDGE('',*,*,#1865,.F.);
#2157=ORIENTED_EDGE('',*,*,#2136,.T.);
#2158=DIRECTION('',(1.,0.,0.));
#2159=VECTOR('',#2158,1.);
#2160=CARTESIAN_POINT('',(13.,3.5,14.5));
#2161=LINE('',#2160,#2159);
#2162=EDGE_CURVE('E1915',#2135,#1978,#2161,.T.);
#2163=ORIENTED_EDGE('',*,*,#2162,.T.);
#2164=ORIENTED_EDGE('',*,*,#1979,.F.);
#2165=EDGE_LOOP('',(#2156,#2157,#2163,#2164));
#2166=FACE_BOUND('',#2165,.T.);
#2167=ADVANCED_FACE('F1919',(#2166),#2122,.T.);
#2168=ORIENTED_EDGE('',*,*,#1888,.F.);
#2169=ORIENTED_EDGE('',*,*,#1993,.F.);
#2170=DIRECTION('',(1.,0.,0.));
#2171=VECTOR('',#2170,1.);
#2172=CARTESIAN_POINT('',(13.,2.,14.5));
#2173=LINE('',#2172,#2171);
#2174=EDGE_CURVE('E1930',#2144,#1986,#2173,.T.);
#2175=ORIENTED_EDGE('',*,*,#2174,.F.);
#2176=ORIENTED_EDGE('',*,*,#2145,.T.);
#2177=EDGE_LOOP('',(#2168,#2169,#2175,#2176));
#2178=FACE_BOUND('',#2177,.T.);
#2179=ADVANCED_FACE('F1934',(#2178),#2110,.T.);
#2180=CARTESIAN_POINT('',(13.,3.5,14.5));
#2181=DIRECTION('',(0.,0.,1.));
#2182=DIRECTION('',(1.,0.,0.));
#2183=AXIS2_PLACEMENT_3D('',#2180,#2181,#2182);
#2184=PLANE('',#2183);
#2185=ORIENTED_EDGE('',*,*,#1987,.F.);
#2186=ORIENTED_EDGE('',*,*,#2162,.F.);
#2187=ORIENTED_EDGE('',*,*,#2151,.T.);
#2188=ORIENTED_EDGE('',*,*,#2174,.T.);
#2189=EDGE_LOOP('',(#2185,#2186,#2187,#2188));
#2190=FACE_BOUND('',#2189,.T.);
#2191=ADVANCED_FACE('F1946',(#2190),#2184,.T.);
#2192=CARTESIAN_POINT('',(19.,5.,10.));
#2193=DIRECTION('',(0.,1.,0.));
#2194=DIRECTION('',(0.,0.,1.));
#2195=AXIS2_PLACEMENT_3D('',#2192,#2193,#2194);
#2196=CONICAL_SURFACE('',#2195,2.,0.785398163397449);
#2197=CARTESIAN_POINT('',(19.,4.621,10.));
#2198=DIRECTION('',(0.,-1.,0.));
#2199=DIRECTION('',(0.,0.,-1.));
#2200=AXIS2_PLACEMENT_3D('',#2197,#2198,#2199);
#2201=CIRCLE('',#2200,1.621);
#2202=CARTESIAN_POINT('',(19.,4.621,8.379));
#2203=VERTEX_POINT('',#2202);
#2204=EDGE_CURVE('E1953',#2203,#2203,#2201,.T.);
#2205=ORIENTED_EDGE('',*,*,#2204,.T.);
#2206=EDGE_LOOP('',(#2205));
#2207=FACE_BOUND('',#2206,.T.);
#2208=ORIENTED_EDGE('',*,*,#166,.F.);
#2209=EDGE_LOOP('',(#2208));
#2210=FACE_BOUND('',#2209,.T.);
#2211=ADVANCED_FACE('F1959',(#2207,#2210),#2196,.F.);
#2212=CARTESIAN_POINT('',(19.,0.,10.));
#2213=DIRECTION('',(0.,-1.,0.));
#2214=DIRECTION('',(0.,0.,-1.));
#2215=AXIS2_PLACEMENT_3D('',#2212,#2213,#2214);
#2216=CYLINDRICAL_SURFACE('',#2215,1.621);
#2217=CARTESIAN_POINT('',(19.,0.379,10.));
#2218=DIRECTION('',(0.,-1.,0.));
#2219=DIRECTION('',(0.,0.,-1.));
#2220=AXIS2_PLACEMENT_3D('',#2217,#2218,#2219);
#2221=CIRCLE('',#2220,1.621);
#2222=CARTESIAN_POINT('',(19.,0.379,8.379));
#2223=VERTEX_POINT('',#2222);
#2224=EDGE_CURVE('E1966',#2223,#2223,#2221,.T.);
#2225=ORIENTED_EDGE('',*,*,#2224,.T.);
#2226=EDGE_LOOP('',(#2225));
#2227=FACE_BOUND('',#2226,.T.);
#2228=ORIENTED_EDGE('',*,*,#2204,.F.);
#2229=EDGE_LOOP('',(#2228));
#2230=FACE_BOUND('',#2229,.T.);
#2231=ADVANCED_FACE('F1972',(#2227,#2230),#2216,.F.);
#2232=CARTESIAN_POINT('',(19.,0.379,10.));
#2233=DIRECTION('',(0.,-1.,0.));
#2234=DIRECTION('',(0.,0.,-1.));
#2235=AXIS2_PLACEMENT_3D('',#2232,#2233,#2234);
#2236=CONICAL_SURFACE('',#2235,1.621,0.785398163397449);
#2237=ORIENTED_EDGE('',*,*,#475,.T.);
#2238=EDGE_LOOP('',(#2237));
#2239=FACE_BOUND('',#2238,.T.);
#2240=ORIENTED_EDGE('',*,*,#2224,.F.);
#2241=EDGE_LOOP('',(#2240));
#2242=FACE_BOUND('',#2241,.T.);
#2243=ADVANCED_FACE('F1983',(#2239,#2242),#2236,.F.);
#2244=CLOSED_SHELL('',(#83,#123,#158,#336,#399,#462,#588,#646,#702,#719,#731,#743,#755,#811,
#823,#835,#866,#888,#900,#912,#938,#950,#962,#974,#1039,#1088,#1137,#1195,#1226,#1248,#1260,
#1272,#1298,#1310,#1322,#1334,#1354,#1374,#1386,#1406,#1426,#1438,#1496,#1545,#1594,#1652,#1683,
#1705,#1717,#1729,#1755,#1767,#1779,#1791,#1811,#1831,#1843,#1892,#1941,#1999,#2023,#2040,#2052,
#2083,#2105,#2117,#2129,#2155,#2167,#2179,#2191,#2211,#2231,#2243));
#2245=MANIFOLD_SOLID_BREP('B1',#2244);
#2246=ADVANCED_BREP_SHAPE_REPRESENTATION('',(#18,#2245),#14);
#2247=SHAPE_DEFINITION_REPRESENTATION(#9,#2246);
ENDSEC;
END-ISO-10303-21;
